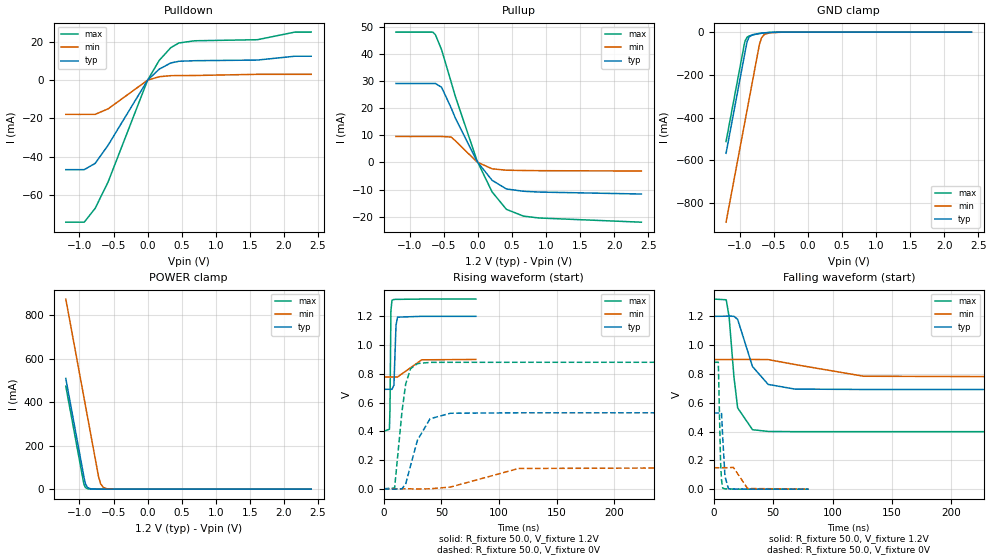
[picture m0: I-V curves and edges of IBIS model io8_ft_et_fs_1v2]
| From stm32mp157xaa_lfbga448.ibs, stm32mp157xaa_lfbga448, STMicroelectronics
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[Model]   io8_ft_et_fs_1v2
Model_type I/O
Polarity   Non-Inverting
Enable   Active-Low
| CAP_THRESHOLD on pad IOFT is "UDTCAPC" :
| Rising=20.00f vddiom   Falling=80.00f vddiom
| C_comp min and max val. don't necessarily correlate with the min and max pvt
| but are the smallest and greatest pad capacitance found.
| var   typ   min   max
C_comp   3.10950pF  3.08865pF  3.12940pF
|C_comp_pullup   1.82115pF  1.58845pF  1.75300pF
|C_comp_pulldown   1.28835pF  1.50020pF  1.37640pF
Vinl = 360.0mV
Vinh = 792.0mV
Vmeas = 600.0mV   | Reference voltage for timing measurements
Cref  = 50.0pF   | Timing specification test load capacitance value
Rref  = 100.0MOhm   | Timing specification test load resistance value
Vref  = 0V   | Timing specification test load voltage
[Model Spec]
| TIME_THRESHOLD on pin ZIV11 is "CMOS" :
| Rising=40.00f vdd   Falling=60.00f vdd
Vinl 463.60000mV 362.60000mV 506.60000mV
Vinh 741.40000mV 545.40000mV 817.40000mV
| variable   typ   min   max
[Temperature Range] 25.0 140.0 -40.0
| variable   typ   min   max
[Voltage Range] 1.2V 900.0mV 1.32V
| variable   typ   min   max
[POWER Clamp Reference] 1.2V 900.0mV 1.32V
| variable   typ   min   max
[GND Clamp Reference] 0V 0V 0V
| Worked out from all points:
|   slope of the pulldown table from 0 to 0.18 V, typ, clamps not added: 30 ohm
|   slope of the pullup table from 0 to 0.18 V, typ, clamps not added: 31.1 ohm
|   GND clamp passes 1 mA (typ) near -0.52 V on its own axis
|   POWER clamp passes 1 mA (typ) near -0.83 V on its own axis
|   rising waveform, R_fixture 50.0, V_fixture 1.2V: 20-80 % time 1.13ns typ, 3.29ns min, 575ps max; typ from 0.692 V to 1.2 V
|   falling waveform, R_fixture 50.0, V_fixture 1.2V: 20-80 % time 12.3ns typ, 33.3ns min, 6.06ns max; typ from 1.2 V to 0.692 V
|   rising waveform, R_fixture 50.0, V_fixture 0V: 20-80 % time 12.3ns typ, 31.1ns min, 6.57ns max; typ from 0 V to 0.529 V
|   falling waveform, R_fixture 50.0, V_fixture 0V: 20-80 % time 2.02ns typ, 4.66ns min, 1.43ns max; typ from 0.529 V to 0 V
[POWER Clamp]
-1.2V     508.8mA    874.1mA    473.5mA
-940mV    66.83mA    432.1mA    31.5mA
-930mV    49.83mA    415.1mA    19.15mA
-910mV    22.88mA    381.1mA    7.077mA
-880mV    7.117mA    330.1mA    1.59mA
-830mV    1.017mA    245.1mA    132uA
-720mV    14.05uA    58.12mA    554nA
-690mV    4.373uA    25.03mA    124.8nA
-650mV    922.5nA    8.136mA    17.23nA
-600mV    132.6nA    1.998mA    1.565nA
-490mV    2.858nA    90.92uA    111.8pA
2.4V      0A         0A         0A
[GND Clamp]
-1.2V     -567.2mA   -889.7mA   -512.2mA
-930mV    -108.2mA   -430.7mA   -53.23mA
-920mV    -91.21mA   -413.7mA   -40.49mA
-890mV    -43.51mA   -362.7mA   -23.59mA
-860mV    -22.57mA   -311.7mA   -17.89mA
-810mV    -12.11mA   -226.7mA   -13.23mA
-710mV    -6.053mA   -57.05mA   -7.064mA
-680mV    -4.908mA   -27.37mA   -5.632mA
-640mV    -3.605mA   -11.51mA   -3.985mA
-560mV    -1.665mA   -3.218mA   -1.61mA
-360mV    -34.72uA   -209.4uA   -9.248uA
2.4V      3.415nA    1.206uA    162.7pA
| variable   typ   min   max
[Pullup Reference] 1.2V 900.0mV 1.32V
| variable   typ   min   max
[Pulldown Reference] 0V 0V 0V
[Pullup]
-1.2V     29.05mA    9.561mA    47.95mA
-660mV    29.05mA    9.561mA    47.95mA
-620mV    29.05mA    9.561mA    46.94mA
-530mV    27.65mA    9.561mA    41.45mA
-390mV    20.07mA    9.347mA    29.59mA
-330mV    16.44mA    8.018mA    24.4mA
-10mV     390.7uA    167.7uA    615.1uA
210mV     -6.527mA   -2.331mA   -10.8mA
420mV     -9.742mA   -2.842mA   -17.23mA
670mV     -10.58mA   -2.95mA    -19.72mA
900mV     -10.88mA   -3.014mA   -20.42mA
2.4V      -11.6mA    -3.141mA   -21.96mA
[Pulldown]
-1.2V     -46.7mA    -17.86mA   -74.13mA
-930mV    -46.7mA    -17.86mA   -74.13mA
-770mV    -43.45mA   -17.86mA   -66.94mA
-580mV    -33.98mA   -14.99mA   -53.18mA
0V        0A         -7pA       0A
170mV     5.742mA    1.791mA    10.3mA
340mV     8.972mA    2.348mA    16.97mA
460mV     9.857mA    2.399mA    19.42mA
690mV     10.15mA    2.431mA    20.56mA
1.61V     10.49mA    3.05mA     21.11mA
2.16V     12.49mA    3.05mA     25.09mA
2.4V      12.49mA    3.05mA     25.09mA
[Ramp]
dV/dt_r 317.39247mV/12.25632ns 89.22182mV/31.10597ns 528.12465mV/6.57236ns
dV/dt_f 304.65151mV/12.34816ns 73.17765mV/33.28345ns 552.41166mV/6.06069ns
R_load = 50.0
| Removed startup time: 0s 0s 0s  .
| Removed end time: 79.9ns.
[Rising Waveform]
R_fixture   = 50.0
V_fixture   = 1.2V
V_fixture_min = 900.0mV
V_fixture_max = 1.32V
0s        692.2mV    778mV      399.3mV
5ns       692.2mV    778mV      414.9mV
5.5ns     692.2mV    778mV      559.5mV
6.3ns     692.3mV    778mV      1.237V
7.2ns     691.9mV    778mV      1.312V
8.9ns     721mV      778mV      1.317V
10.7ns    1.135V     778mV      1.318V
12ns      1.194V     778mV      1.318V
33ns      1.2V       897.3mV    1.32V
79.9ns    1.2V       899.9mV    1.32V
| Removed startup time: 0s 0s 0s  .
| Removed end time: 399.9ns.
[Falling Waveform]
R_fixture   = 50.0
V_fixture   = 1.2V
V_fixture_min = 900.0mV
V_fixture_max = 1.32V
0s        1.2V       900mV      1.32V
10.5ns    1.201V     900mV      1.315V
12.9ns    1.202V     900mV      1.197V
17ns      1.2V       900.7mV    777.2mV
20.1ns    1.179V     900.8mV    564.1mV
32.6ns    851.3mV    900.6mV    412.8mV
45.8ns    727.1mV    899.8mV    400.9mV
68.3ns    695mV      865.5mV    399.3mV
126.1ns   692.2mV    784.1mV    399.3mV
399.9ns   692.2mV    778mV      399.3mV
| Removed startup time: 0s 0s 0s  .
| Removed end time: 399.9ns.
[Rising Waveform]
R_fixture   = 50.0
V_fixture   = 0V
V_fixture_min = 0V
V_fixture_max = 0V
0s        705.9nV    1.001uV    -336.9nV
9.5ns     -2.463mV   1.104uV    6.013mV
15.9ns    303.6uV    1.163uV    538.3mV
19.1ns    34.41mV    -285.2nV   729.4mV
23.3ns    160.5mV    -10.8uV    835.7mV
29.3ns    338.2mV    -1.524mV   871.3mV
40.2ns    487.2mV    68.63uV    879.5mV
57.9ns    525.7mV    12.27mV    880.1mV
117ns     528.8mV    141.5mV    880.2mV
399.9ns   529mV      148.7mV    880.2mV
| Removed startup time: 0s 0s 0s  .
| Removed end time: 79.9ns.
[Falling Waveform]
R_fixture   = 50.0
V_fixture   = 0V
V_fixture_min = 0V
V_fixture_max = 0V
0s        529mV      148.8mV    880.2mV
3.8ns     529mV      148.8mV    881.8mV
5.7ns     531.5mV    148.8mV    190.1mV
6.5ns     532mV      148.8mV    66.18mV
7.5ns     362mV      148.8mV    7.005mV
9.4ns     89.88mV    148.8mV    2.362mV
12.3ns    3.334mV    148.8mV    1.339mV
16.5ns    968.3uV    151.6mV    522uV
28.4ns    336.2uV    4.682mV    61.45uV
79.9ns    -216.7nV   106.4uV    2.402uV
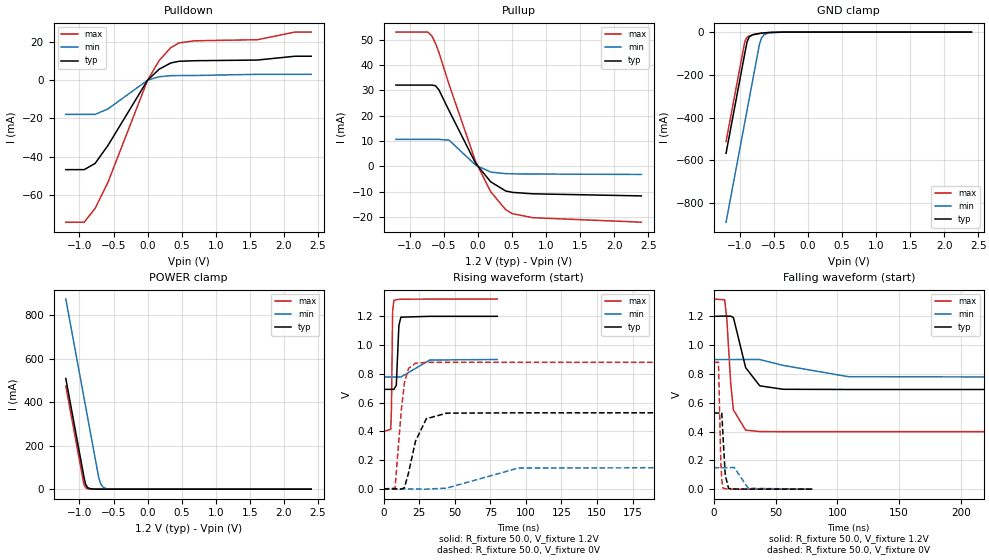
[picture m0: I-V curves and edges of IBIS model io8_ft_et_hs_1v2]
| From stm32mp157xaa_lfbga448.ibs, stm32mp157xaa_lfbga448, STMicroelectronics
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[Model]   io8_ft_et_hs_1v2
Model_type I/O
Polarity   Non-Inverting
Enable   Active-Low
| CAP_THRESHOLD on pad IOFT is "UDTCAPC" :
| Rising=20.00f vddiom   Falling=80.00f vddiom
| C_comp min and max val. don't necessarily correlate with the min and max pvt
| but are the smallest and greatest pad capacitance found.
| var   typ   min   max
C_comp   3.10950pF  3.08870pF  3.12940pF
|C_comp_pullup   1.82115pF  1.58835pF  1.75300pF
|C_comp_pulldown   1.28835pF  1.50035pF  1.37640pF
Vinl = 360.0mV
Vinh = 792.0mV
Vmeas = 600.0mV   | Reference voltage for timing measurements
Cref  = 50.0pF   | Timing specification test load capacitance value
Rref  = 100.0MOhm   | Timing specification test load resistance value
Vref  = 0V   | Timing specification test load voltage
[Model Spec]
| TIME_THRESHOLD on pin ZIV11 is "CMOS" :
| Rising=40.00f vdd   Falling=60.00f vdd
Vinl 463.60000mV 362.60000mV 506.60000mV
Vinh 741.40000mV 545.40000mV 817.40000mV
| variable   typ   min   max
[Temperature Range] 25.0 140.0 -40.0
| variable   typ   min   max
[Voltage Range] 1.2V 900.0mV 1.32V
| variable   typ   min   max
[POWER Clamp Reference] 1.2V 900.0mV 1.32V
| variable   typ   min   max
[GND Clamp Reference] 0V 0V 0V
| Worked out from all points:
|   slope of the pulldown table from 0 to 0.18 V, typ, clamps not added: 30 ohm
|   slope of the pullup table from 0 to 0.18 V, typ, clamps not added: 31.1 ohm
|   GND clamp passes 1 mA (typ) near -0.52 V on its own axis
|   POWER clamp passes 1 mA (typ) near -0.83 V on its own axis
|   rising waveform, R_fixture 50.0, V_fixture 1.2V: 20-80 % time 1.13ns typ, 3.33ns min, 581ps max; typ from 0.692 V to 1.2 V
|   falling waveform, R_fixture 50.0, V_fixture 1.2V: 20-80 % time 9.04ns typ, 24.3ns min, 4.4ns max; typ from 1.2 V to 0.692 V
|   rising waveform, R_fixture 50.0, V_fixture 0V: 20-80 % time 8.16ns typ, 20.6ns min, 4.43ns max; typ from 0 V to 0.529 V
|   falling waveform, R_fixture 50.0, V_fixture 0V: 20-80 % time 2.01ns typ, 4.63ns min, 1.42ns max; typ from 0.529 V to 0 V
[POWER Clamp]
-1.2V     508.8mA    874.1mA    473.5mA
-940mV    66.83mA    432.1mA    31.5mA
-930mV    49.83mA    415.1mA    19.15mA
-910mV    22.88mA    381.1mA    7.077mA
-880mV    7.117mA    330.1mA    1.59mA
-830mV    1.017mA    245.1mA    132uA
-720mV    14.05uA    58.12mA    554nA
-690mV    4.373uA    25.03mA    124.8nA
-650mV    922.5nA    8.136mA    17.23nA
-600mV    132.6nA    1.998mA    1.565nA
-490mV    2.858nA    90.92uA    111.8pA
2.4V      0A         0A         0A
[GND Clamp]
-1.2V     -567.2mA   -889.7mA   -512.2mA
-930mV    -108.2mA   -430.7mA   -53.23mA
-920mV    -91.21mA   -413.7mA   -40.49mA
-890mV    -43.51mA   -362.7mA   -23.59mA
-860mV    -22.57mA   -311.7mA   -17.89mA
-810mV    -12.11mA   -226.7mA   -13.23mA
-710mV    -6.053mA   -57.05mA   -7.064mA
-680mV    -4.908mA   -27.37mA   -5.632mA
-640mV    -3.605mA   -11.51mA   -3.985mA
-560mV    -1.665mA   -3.218mA   -1.61mA
-360mV    -34.72uA   -209.4uA   -9.248uA
2.4V      3.415nA    1.206uA    162.7pA
| variable   typ   min   max
[Pullup Reference] 1.2V 900.0mV 1.32V
| variable   typ   min   max
[Pulldown Reference] 0V 0V 0V
[Pullup]
-1.2V     32.07mA    10.67mA    52.96mA
-730mV    32.07mA    10.67mA    52.96mA
-670mV    32.07mA    10.67mA    51.32mA
-620mV    31.82mA    10.67mA    48.54mA
-570mV    30.22mA    10.67mA    45.01mA
-420mV    21.97mA    10.36mA    32.26mA
-30mV     1.194mA    519uA      1.871mA
190mV     -6.046mA   -2.203mA   -9.95mA
410mV     -9.663mA   -2.836mA   -17.03mA
510mV     -10.21mA   -2.889mA   -18.61mA
810mV     -10.78mA   -2.991mA   -20.19mA
2.4V      -11.6mA    -3.141mA   -21.96mA
[Pulldown]
-1.2V     -46.7mA    -17.86mA   -74.13mA
-930mV    -46.7mA    -17.86mA   -74.13mA
-770mV    -43.45mA   -17.86mA   -66.94mA
-580mV    -33.98mA   -14.99mA   -53.18mA
0V        0A         -7pA       0A
170mV     5.742mA    1.791mA    10.3mA
340mV     8.972mA    2.348mA    16.97mA
460mV     9.857mA    2.399mA    19.42mA
690mV     10.15mA    2.431mA    20.56mA
1.61V     10.49mA    3.05mA     21.11mA
2.16V     12.49mA    3.05mA     25.09mA
2.4V      12.49mA    3.05mA     25.09mA
[Ramp]
dV/dt_r 317.40685mV/8.16413ns 89.2458mV/20.59137ns 528.12535mV/4.43286ns
dV/dt_f 304.65929mV/9.03397ns 73.17635mV/24.3405ns 552.41075mV/4.40029ns
R_load = 50.0
| Removed startup time: 0s 0s 0s  .
| Removed end time: 79.9ns.
[Rising Waveform]
R_fixture   = 50.0
V_fixture   = 1.2V
V_fixture_min = 900.0mV
V_fixture_max = 1.32V
0s        692.2mV    778mV      399.3mV
5ns       692.2mV    778mV      414.9mV
5.5ns     692.2mV    778mV      562mV
6.3ns     692.3mV    778mV      1.236V
7.2ns     691.9mV    778mV      1.311V
8.9ns     721.1mV    778mV      1.316V
10.7ns    1.135V     778mV      1.318V
12.1ns    1.194V     778mV      1.319V
32.4ns    1.2V       896.2mV    1.32V
79.9ns    1.2V       899.9mV    1.32V
| Removed startup time: 0s 0s 0s  .
| Removed end time: 399.9ns.
[Falling Waveform]
R_fixture   = 50.0
V_fixture   = 1.2V
V_fixture_min = 900.0mV
V_fixture_max = 1.32V
0s        1.2V       900mV      1.32V
8.8ns     1.202V     900mV      1.315V
10.6ns    1.201V     900mV      1.178V
13.7ns    1.201V     900mV      737mV
15.9ns    1.192V     900mV      550.3mV
25.8ns    844mV      900.4mV    409.9mV
37.2ns    717.7mV    900.2mV    400.2mV
56.2ns    693.5mV    859.4mV    399.3mV
109.3ns   692.2mV    780.6mV    399.3mV
399.9ns   692.2mV    778mV      399.3mV
| Removed startup time: 0s 0s 0s  .
| Removed end time: 399.9ns.
[Rising Waveform]
R_fixture   = 50.0
V_fixture   = 0V
V_fixture_min = 0V
V_fixture_max = 0V
0s        678.3nV    993.2nV    -351.9nV
8ns       -1.184uV   1.103uV    5.393mV
12.4ns    -1.772mV   1.102uV    548.2mV
14.6ns    7.992mV    1.101uV    736.7mV
17.5ns    112.1mV    -194.9nV   838.7mV
22.4ns    331.8mV    33.33uV    874.1mV
30ns      487.8mV    -1.8mV     879.7mV
44.3ns    526.8mV    5.42mV     880.1mV
94.9ns    528.9mV    145.7mV    880.2mV
399.9ns   529mV      148.7mV    880.2mV
| Removed startup time: 0s 0s 0s  .
| Removed end time: 79.9ns.
[Falling Waveform]
R_fixture   = 50.0
V_fixture   = 0V
V_fixture_min = 0V
V_fixture_max = 0V
0s        529mV      148.8mV    880.2mV
3.8ns     529mV      148.8mV    881.2mV
5.7ns     531.3mV    148.8mV    186.7mV
6.5ns     531.1mV    148.8mV    64.4mV
7.4ns     379.6mV    148.8mV    8.542mV
9.3ns     95.82mV    148.8mV    2.783mV
12ns      4.652mV    148.8mV    1.031mV
16.5ns    1.257mV    151.2mV    291.7uV
27.9ns    207.9uV    5.932mV    20.21uV
79.9ns    611.7nV    56.41uV    983.4nV
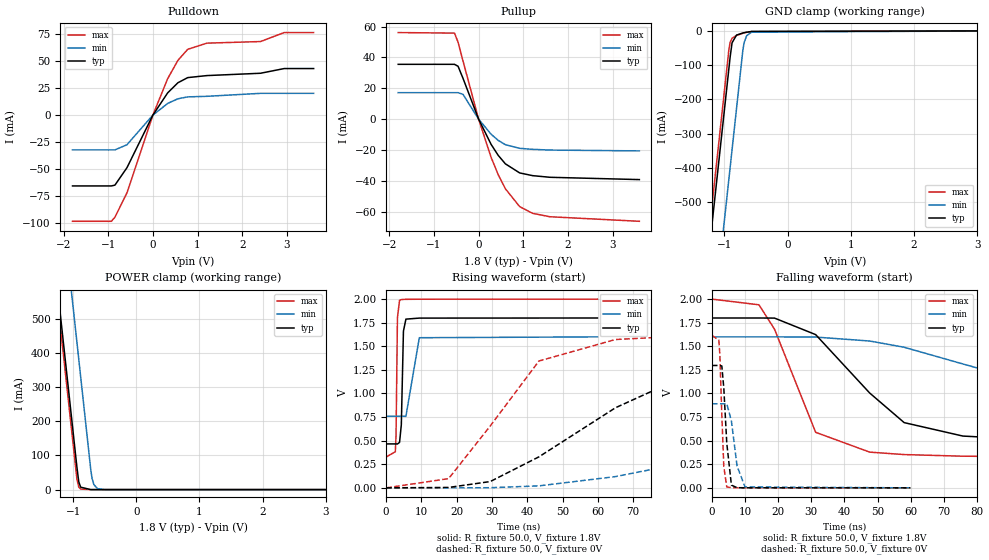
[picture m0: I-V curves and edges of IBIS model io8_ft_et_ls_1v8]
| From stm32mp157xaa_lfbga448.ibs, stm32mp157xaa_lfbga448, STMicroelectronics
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[Model]   io8_ft_et_ls_1v8
Model_type I/O
Polarity   Non-Inverting
Enable   Active-Low
| CAP_THRESHOLD on pad IOFT is "UDTCAPC" :
| Rising=20.00f vddiom   Falling=80.00f vddiom
| C_comp min and max val. don't necessarily correlate with the min and max pvt
| but are the smallest and greatest pad capacitance found.
| var   typ   min   max
C_comp   3.43098pF  3.42356pF  3.49925pF
|C_comp_pullup   1.96705pF  2.05925pF  1.91840pF
|C_comp_pulldown   1.46393pF  1.36431pF  1.58085pF
Vinl = 640.0mV
Vinh = 1.2V
Vmeas = 900.0mV   | Reference voltage for timing measurements
Cref  = 50.0pF   | Timing specification test load capacitance value
Rref  = 100.0MOhm   | Timing specification test load resistance value
Vref  = 0V   | Timing specification test load voltage
[Model Spec]
| TIME_THRESHOLD on pin ZIV11 is "CMOS" :
| Rising=40.00f vdd   Falling=60.00f vdd
Vinl 738.60000mV 665.60000mV 824.60000mV
Vinh 1.04640V 924.40000mV 1.13940V
| variable   typ   min   max
[Temperature Range] 25.0 140.0 -40.0
| variable   typ   min   max
[Voltage Range] 1.8V 1.6V 2.0V
| variable   typ   min   max
[POWER Clamp Reference] 1.8V 1.6V 2.0V
| variable   typ   min   max
[GND Clamp Reference] 0V 0V 0V
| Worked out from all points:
|   slope of the pulldown table from 0 to 0.27 V, typ, clamps not added: 16 ohm
|   slope of the pullup table from 0 to 0.27 V, typ, clamps not added: 17 ohm
|   GND clamp passes 1 mA (typ) near -0.52 V on its own axis
|   POWER clamp passes 1 mA (typ) near -0.83 V on its own axis
|   rising waveform, R_fixture 50.0, V_fixture 1.8V: 20-80 % time 427ps typ, 900ps min, 292ps max; typ from 0.466 V to 1.8 V
|   falling waveform, R_fixture 50.0, V_fixture 1.8V: 20-80 % time 21.4ns typ, 55.5ns min, 10.8ns max; typ from 1.8 V to 0.466 V
|   rising waveform, R_fixture 50.0, V_fixture 0V: 20-80 % time 35.1ns typ, 77.6ns min, 18.5ns max; typ from 0 V to 1.3 V
|   falling waveform, R_fixture 50.0, V_fixture 0V: 20-80 % time 1.35ns typ, 2.08ns min, 940ps max; typ from 1.3 V to 0 V
[POWER Clamp]
-1.8V     1.529A     1.894A     1.494A
-940mV    66.83mA    432.1mA    31.5mA
-910mV    22.88mA    381.1mA    7.077mA
-880mV    7.117mA    330.1mA    1.59mA
-720mV    14.05uA    58.12mA    554nA
-700mV    6.453uA    33.14mA    205nA
-670mV    2.008uA    14.27mA    46.29nA
-610mV    195.5nA    2.645mA    2.508nA
-500mV    3.962nA    120.4uA    139.7pA
3.6V      0A         0A         0A
[GND Clamp]
-1.8V     -1.588A    -1.91A     -1.533A
-1.26V    -670.3mA   -992.4mA   -614.9mA
-1.2V     -568.3mA   -890.4mA   -512.9mA
-930mV    -109.3mA   -431.4mA   -53.86mA
-910mV    -75.33mA   -397.4mA   -32.91mA
-880mV    -34.88mA   -346.4mA   -21.56mA
-810mV    -12.56mA   -227.4mA   -13.55mA
-710mV    -6.275mA   -57.63mA   -7.234mA
-690mV    -5.461mA   -35.21mA   -6.234mA
-650mV    -4.039mA   -14.43mA   -4.463mA
-570mV    -1.908mA   -3.832mA   -1.869mA
3.6V      5.084nA    1.599uA    245.6pA
| variable   typ   min   max
[Pullup Reference] 1.8V 1.6V 2.0V
| variable   typ   min   max
[Pulldown Reference] 0V 0V 0V
[Pullup]
-1.8V     35.55mA    17.17mA    56.15mA
-540mV    35.55mA    17.17mA    55.8mA
-460mV    34.29mA    17.17mA    49.92mA
-350mV    26.53mA    16.1mA     37.8mA
0V        7.41pA     1.33nA     4.294pA
280mV     -16.39mA   -9.814mA   -24.79mA
440mV     -23.55mA   -13.81mA   -36.1mA
600mV     -29.02mA   -16.6mA    -45.2mA
920mV     -34.92mA   -18.96mA   -56.79mA
1.21V     -36.68mA   -19.61mA   -61.13mA
1.6V      -37.75mA   -20.08mA   -63.35mA
3.6V      -39.24mA   -20.63mA   -66.3mA
[Pulldown]
-1.8V     -65.8mA    -32.31mA   -98.64mA
-930mV    -65.8mA    -32.31mA   -98.64mA
-850mV    -65.04mA   -32.31mA   -94.81mA
-580mV    -48.83mA   -27.49mA   -72.14mA
0V        0A         -4pA       0A
330mV     20.59mA    10.79mA    33.74mA
560mV     30.02mA    15.15mA    50.81mA
780mV     34.81mA    16.9mA     61.1mA
1.21V     36.69mA    17.44mA    66.81mA
2.41V     38.85mA    20.19mA    68.31mA
2.94V     43.21mA    20.19mA    76.64mA
3.6V      43.21mA    20.19mA    76.64mA
[Ramp]
dV/dt_r 777.9091mV/35.05865ns 534.07155mV/77.63022ns 970.12301mV/18.51058ns
dV/dt_f 800.59623mV/21.38691ns 504.68342mV/55.54374ns 1.00395V/10.83689ns
R_load = 50.0
| Removed startup time: 0s 0s 0s  .
| Removed end time: 59.9ns.
[Rising Waveform]
R_fixture   = 50.0
V_fixture   = 1.8V
V_fixture_min = 1.6V
V_fixture_max = 2.0V
0s        465.7mV    758.8mV    326.8mV
2.6ns     465.7mV    758.8mV    382.8mV
2.8ns     465.7mV    758.8mV    549.6mV
3.2ns     464.7mV    758.8mV    1.803V
3.8ns     482.2mV    758.8mV    1.988V
4.3ns     669.8mV    758.8mV    1.995V
4.9ns     1.661V     758.9mV    1.997V
5.6ns     1.788V     757.8mV    1.998V
9.4ns     1.799V     1.591V     1.999V
59.9ns    1.8V       1.6V       2V
| Removed startup time: 0s 0s 0s  .
| Removed end time: 499.9ns.
[Falling Waveform]
R_fixture   = 50.0
V_fixture   = 1.8V
V_fixture_min = 1.6V
V_fixture_max = 2.0V
0s        1.8V       1.6V       2V
14.2ns    1.8V       1.6V       1.94V
18.9ns    1.799V     1.6V       1.681V
31.3ns    1.624V     1.598V     588.7mV
47.6ns    1.005V     1.556V     378.6mV
58ns      691.4mV    1.49V      352.8mV
75.7ns    549mV      1.313V     335.5mV
109.6ns   485.9mV    980.8mV    328mV
161.9ns   468.8mV    820.4mV    326.8mV
499.9ns   465.7mV    758.9mV    326.7mV
| Removed startup time: 0s 0s 0s  .
| Removed end time: 499.9ns.
[Rising Waveform]
R_fixture   = 50.0
V_fixture   = 0V
V_fixture_min = 0V
V_fixture_max = 0V
0s        674.6nV    584.2nV    -417.9nV
17.7ns    4.217mV    -80.05uV   97.74mV
29.5ns    66.72mV    1.451mV    655.4mV
43.3ns    328.4mV    20.97mV    1.344V
65ns      848.5mV    119.3mV    1.572V
79.2ns    1.09V      224.3mV    1.599V
95.2ns    1.208V     356.2mV    1.61V
142.1ns   1.284V     673.6mV    1.617V
190.8ns   1.295V     820.1mV    1.617V
499.9ns   1.297V     890.1mV    1.617V
| Removed startup time: 0s 0s 0s  .
| Removed end time: 59.9ns.
[Falling Waveform]
R_fixture   = 50.0
V_fixture   = 0V
V_fixture_min = 0V
V_fixture_max = 0V
0s        1.297V     890.4mV    1.617V
2.1ns     1.297V     890.4mV    1.565V
2.4ns     1.296V     890.4mV    1.418V
3ns       1.292V     890.4mV    777.8mV
3.6ns     1.059V     890.4mV    226.5mV
4.5ns     471mV      893.5mV    9.77mV
5.9ns     28.78mV    706.6mV    2.065mV
7.6ns     1.869mV    231.5mV    1.317mV
10ns      814.2uV    9.749mV    1.005mV
59.9ns    102uV      193.7uV    43.17uV
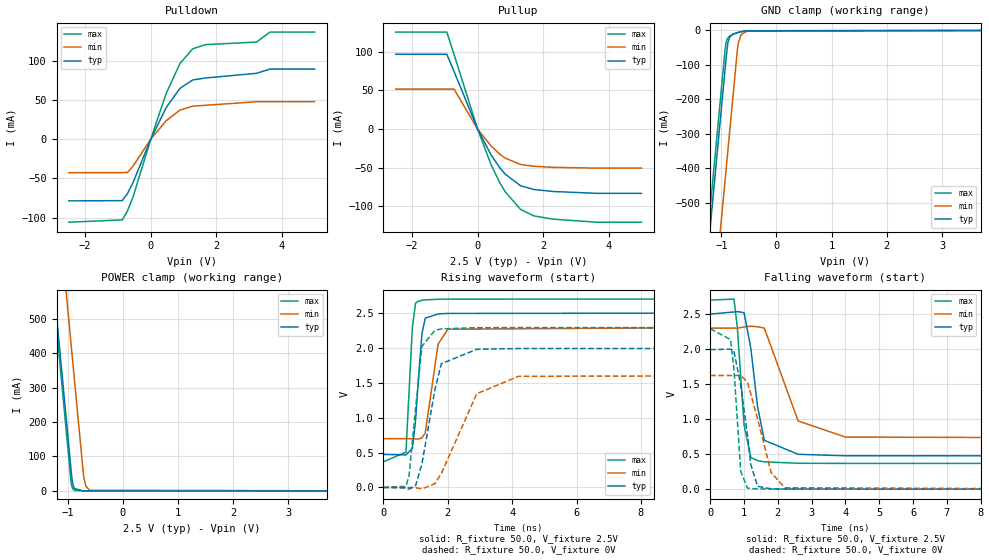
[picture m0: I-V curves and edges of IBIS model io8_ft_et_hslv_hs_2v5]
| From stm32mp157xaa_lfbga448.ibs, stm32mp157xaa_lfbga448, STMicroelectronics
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[Model]   io8_ft_et_hslv_hs_2v5
Model_type I/O
Polarity   Non-Inverting
Enable   Active-Low
| CAP_THRESHOLD on pad IOFT is "UDTCAPC" :
| Rising=20.00f vddiom   Falling=80.00f vddiom
| C_comp min and max val. don't necessarily correlate with the min and max pvt
| but are the smallest and greatest pad capacitance found.
| var   typ   min   max
C_comp   3.59839pF  3.56215pF  3.65635pF
|C_comp_pullup   2.12240pF  2.18495pF  2.03935pF
|C_comp_pulldown   1.47599pF  1.37720pF  1.61700pF
Vinl = 920.0mV
Vinh = 1.62V
Vmeas = 1.25V   | Reference voltage for timing measurements
Cref  = 50.0pF   | Timing specification test load capacitance value
Rref  = 100.0MOhm   | Timing specification test load resistance value
Vref  = 0V   | Timing specification test load voltage
[Model Spec]
| TIME_THRESHOLD on pin ZIV11 is "CMOS" :
| Rising=40.00f vdd   Falling=60.00f vdd
Vinl 1.03860V 964.60000mV 1.11860V
Vinh 1.36340V 1.26240V 1.44140V
| variable   typ   min   max
[Temperature Range] 25.0 140.0 -40.0
| variable   typ   min   max
[Voltage Range] 2.5V 2.3V 2.7V
| variable   typ   min   max
[POWER Clamp Reference] 2.5V 2.3V 2.7V
| variable   typ   min   max
[GND Clamp Reference] 0V 0V 0V
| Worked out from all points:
|   slope of the pulldown table from 0 to 0.375 V, typ, clamps not added: 11.3 ohm
|   slope of the pullup table from 0 to 0.375 V, typ, clamps not added: 12.3 ohm
|   GND clamp passes 1 mA (typ) near -0.52 V on its own axis
|   POWER clamp passes 1 mA (typ) near -0.83 V on its own axis
|   rising waveform, R_fixture 50.0, V_fixture 2.5V: 20-80 % time 200ps typ, 261ps min, 151ps max; typ from 0.473 V to 2.5 V
|   falling waveform, R_fixture 50.0, V_fixture 2.5V: 20-80 % time 323ps typ, 661ps min, 212ps max; typ from 2.5 V to 0.473 V
|   rising waveform, R_fixture 50.0, V_fixture 0V: 20-80 % time 462ps typ, 914ps min, 287ps max; typ from 0 V to 1.99 V
|   falling waveform, R_fixture 50.0, V_fixture 0V: 20-80 % time 323ps typ, 518ps min, 198ps max; typ from 1.99 V to 0 V
[POWER Clamp]
-2.5V     2.719A     3.084A     2.683A
-1.38V    814.8mA    1.18A      779.5mA
-1.28V    644.8mA    1.01A      609.5mA
-1.07V    287.8mA    653.1mA    252.5mA
-940mV    66.83mA    432.1mA    31.5mA
-930mV    49.83mA    415.1mA    19.15mA
-910mV    22.88mA    381.1mA    7.077mA
-880mV    7.117mA    330.1mA    1.59mA
-710mV    9.523uA    43.89mA    337nA
-670mV    2.009uA    14.27mA    46.32nA
-600mV    133.1nA    1.998mA    1.613nA
5V        0A         0A         0A
[GND Clamp]
-2.5V     -2.779A    -3.101A    -2.723A
-1.26V    -670.8mA   -992.7mA   -614.5mA
-930mV    -109.8mA   -431.7mA   -53.54mA
-910mV    -75.83mA   -397.7mA   -32.67mA
-880mV    -35.28mA   -346.7mA   -21.39mA
-850mV    -20.07mA   -295.7mA   -16.99mA
-790mV    -10.9mA    -193.7mA   -12.02mA
-710mV    -6.374mA   -57.93mA   -7.219mA
-690mV    -5.545mA   -35.45mA   -6.225mA
-640mV    -3.775mA   -11.96mA   -4.068mA
-540mV    -1.354mA   -2.661mA   -1.223mA
5V        7.033nA    2.148uA    347.4pA
| variable   typ   min   max
[Pullup Reference] 2.5V 2.3V 2.7V
| variable   typ   min   max
[Pulldown Reference] 0V 0V 0V
[Pullup]
-2.5V     96.71mA    51.69mA    125.4mA
-940mV    96.71mA    51.69mA    125.4mA
-720mV    74.67mA    51.69mA    96.58mA
0V        9.19pA     1.4nA      5.79pA
410mV     -33.27mA   -21.82mA   -45.98mA
680mV     -50.17mA   -32.54mA   -69.6mA
840mV     -58.2mA    -37.47mA   -80.99mA
1.31V     -73.24mA   -45.77mA   -103.8mA
1.71V     -78.05mA   -48.05mA   -112.2mA
2.29V     -80.67mA   -49.47mA   -116.4mA
3.63V     -83.07mA   -50.51mA   -120.4mA
5V        -83.07mA   -50.51mA   -120.4mA
[Pulldown]
-2.5V     -78.63mA   -42.6mA    -105.8mA
-870mV    -78.28mA   -42.6mA    -102.9mA
-710mV    -69.32mA   -42.37mA   -91.24mA
-540mV    -55.23mA   -34.22mA   -73.64mA
0V        0A         -3pA       10fA
470mV     40.29mA    23.69mA    58.27mA
890mV     64.85mA    37.11mA    96.49mA
1.28V     75.62mA    42.24mA    115.4mA
1.67V     78.14mA    43.3mA     120.7mA
3.23V     84.11mA    47.89mA    124mA
3.64V     89.51mA    47.89mA    136.7mA
5V        89.51mA    47.89mA    136.7mA
[Ramp]
dV/dt_r 1.19557V/459.39233ps 973.59944mV/910.50009ps 1.37498V/274.75527ps
dV/dt_f 1.21605V/318.55635ps 960.47162mV/655.26821ps 1.39952V/201.72225ps
R_load = 50.0
| Removed startup time: 0s 0s 0s  .
| Removed end time: 12.9ns.
[Rising Waveform]
R_fixture   = 50.0
V_fixture   = 2.5V
V_fixture_min = 2.3V
V_fixture_max = 2.7V
0s        473.2mV    699.2mV    367.5mV
700ps     466mV      699.2mV    505.3mV
900ps     561.3mV    699.7mV    2.294V
1ns       959.7mV    695.6mV    2.642V
1.1ns     1.633V     694.1mV    2.672V
1.2ns     2.21V      711.4mV    2.683V
1.3ns     2.426V     781.5mV    2.688V
1.7ns     2.487V     2.054V     2.697V
2ns       2.494V     2.267V     2.699V
12.9ns    2.5V       2.3V       2.7V
| Removed startup time: 0s 0s 0s  .
| Removed end time: 35.9ns.
[Falling Waveform]
R_fixture   = 50.0
V_fixture   = 2.5V
V_fixture_min = 2.3V
V_fixture_max = 2.7V
0s        2.5V       2.3V       2.7V
700ps     2.531V     2.3V       2.715V
800ps     2.536V     2.299V     2.313V
1ns       2.52V      2.317V     918.7mV
1.2ns     2.012V     2.328V     452.7mV
1.4ns     1.175V     2.319V     407.8mV
1.6ns     697.7mV    2.3V       390.7mV
2.6ns     498.1mV    973.7mV    369.9mV
4ns       476.5mV    744.3mV    367.8mV
35.9ns    473.2mV    699.2mV    367.5mV
| Removed startup time: 0s 0s 0s  .
| Removed end time: 35.9ns.
[Rising Waveform]
R_fixture   = 50.0
V_fixture   = 0V
V_fixture_min = 0V
V_fixture_max = 0V
0s        50.41nV    -366nV     -6.381uV
700ps     -8.405mV   -165.7uV   14.5mV
800ps     -24.9mV    -148.8uV   177.8mV
1ns       27.11mV    -3.101mV   1.137V
1.2ns     341.7mV    -21.82mV   2.023V
1.6ns     1.403V     54.6mV     2.252V
1.8ns     1.773V     199.8mV    2.272V
2.9ns     1.98V      1.343V     2.29V
4.2ns     1.991V     1.593V     2.291V
35.9ns    1.993V     1.623V     2.292V
| Removed startup time: 0s 0s 0s  .
| Removed end time: 12.9ns.
[Falling Waveform]
R_fixture   = 50.0
V_fixture   = 0V
V_fixture_min = 0V
V_fixture_max = 0V
0s        1.993V     1.623V     2.292V
600ps     2V         1.623V     2.136V
700ps     1.971V     1.622V     1.719V
900ps     1.487V     1.629V     257.5mV
1.1ns     775mV      1.527V     14.59mV
1.2ns     351.5mV    1.359V     7.748mV
1.4ns     40.6mV     1.003V     3.886mV
1.8ns     4.779mV    239.4mV    2.09mV
2.2ns     2.674mV    21.12mV    1.122mV
12.9ns    17.76uV    39.62uV    6.471uV
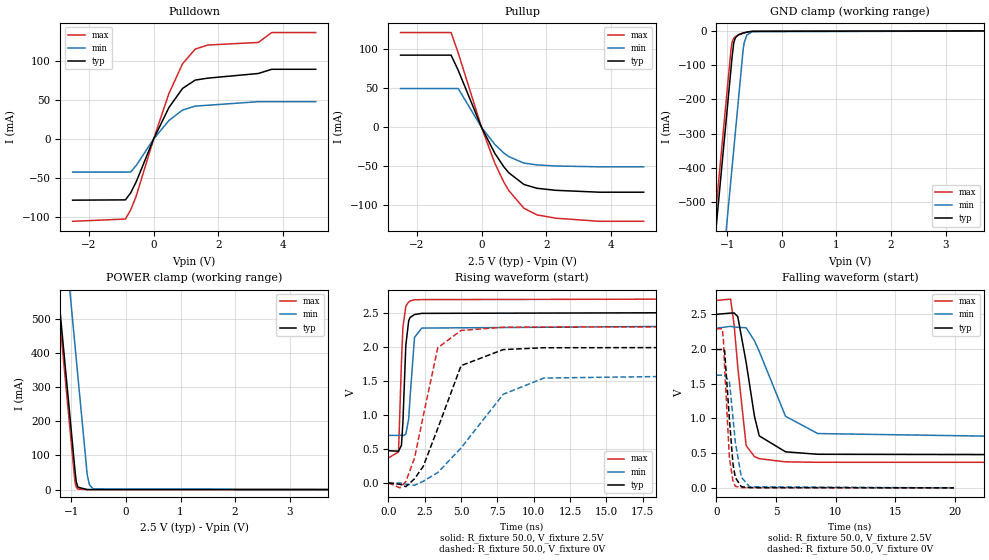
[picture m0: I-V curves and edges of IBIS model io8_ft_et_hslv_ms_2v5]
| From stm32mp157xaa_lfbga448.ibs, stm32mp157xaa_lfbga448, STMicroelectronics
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[Model]   io8_ft_et_hslv_ms_2v5
Model_type I/O
Polarity   Non-Inverting
Enable   Active-Low
| CAP_THRESHOLD on pad IOFT is "UDTCAPC" :
| Rising=20.00f vddiom   Falling=80.00f vddiom
| C_comp min and max val. don't necessarily correlate with the min and max pvt
| but are the smallest and greatest pad capacitance found.
| var   typ   min   max
C_comp   3.59839pF  3.56215pF  3.65635pF
|C_comp_pullup   2.12240pF  2.18495pF  2.03935pF
|C_comp_pulldown   1.47599pF  1.37720pF  1.61700pF
Vinl = 920.0mV
Vinh = 1.62V
Vmeas = 1.25V   | Reference voltage for timing measurements
Cref  = 50.0pF   | Timing specification test load capacitance value
Rref  = 100.0MOhm   | Timing specification test load resistance value
Vref  = 0V   | Timing specification test load voltage
[Model Spec]
| TIME_THRESHOLD on pin ZIV11 is "CMOS" :
| Rising=40.00f vdd   Falling=60.00f vdd
Vinl 1.03860V 964.60000mV 1.11860V
Vinh 1.36340V 1.26240V 1.44140V
| variable   typ   min   max
[Temperature Range] 25.0 140.0 -40.0
| variable   typ   min   max
[Voltage Range] 2.5V 2.3V 2.7V
| variable   typ   min   max
[POWER Clamp Reference] 2.5V 2.3V 2.7V
| variable   typ   min   max
[GND Clamp Reference] 0V 0V 0V
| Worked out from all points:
|   slope of the pulldown table from 0 to 0.375 V, typ, clamps not added: 11.3 ohm
|   slope of the pullup table from 0 to 0.375 V, typ, clamps not added: 12.3 ohm
|   GND clamp passes 1 mA (typ) near -0.52 V on its own axis
|   POWER clamp passes 1 mA (typ) near -0.83 V on its own axis
|   rising waveform, R_fixture 50.0, V_fixture 2.5V: 20-80 % time 232ps typ, 273ps min, 230ps max; typ from 0.473 V to 2.5 V
|   falling waveform, R_fixture 50.0, V_fixture 2.5V: 20-80 % time 1.14ns typ, 2.29ns min, 739ps max; typ from 2.5 V to 0.473 V
|   rising waveform, R_fixture 50.0, V_fixture 0V: 20-80 % time 1.92ns typ, 3.56ns min, 1.28ns max; typ from 0 V to 1.99 V
|   falling waveform, R_fixture 50.0, V_fixture 0V: 20-80 % time 498ps typ, 638ps min, 413ps max; typ from 1.99 V to 0 V
[POWER Clamp]
-2.5V     2.719A     3.084A     2.683A
-1.38V    814.8mA    1.18A      779.5mA
-1.28V    644.8mA    1.01A      609.5mA
-1.07V    287.8mA    653.1mA    252.5mA
-940mV    66.83mA    432.1mA    31.5mA
-930mV    49.83mA    415.1mA    19.15mA
-910mV    22.88mA    381.1mA    7.077mA
-880mV    7.117mA    330.1mA    1.59mA
-710mV    9.523uA    43.89mA    337nA
-670mV    2.009uA    14.27mA    46.32nA
-600mV    133.1nA    1.998mA    1.613nA
5V        0A         0A         0A
[GND Clamp]
-2.5V     -2.779A    -3.101A    -2.723A
-1.26V    -670.8mA   -992.7mA   -614.5mA
-930mV    -109.8mA   -431.7mA   -53.54mA
-910mV    -75.83mA   -397.7mA   -32.67mA
-880mV    -35.28mA   -346.7mA   -21.39mA
-850mV    -20.07mA   -295.7mA   -16.99mA
-790mV    -10.9mA    -193.7mA   -12.02mA
-710mV    -6.374mA   -57.93mA   -7.219mA
-690mV    -5.545mA   -35.45mA   -6.225mA
-640mV    -3.775mA   -11.96mA   -4.068mA
-540mV    -1.354mA   -2.661mA   -1.223mA
5V        7.033nA    2.148uA    347.4pA
| variable   typ   min   max
[Pullup Reference] 2.5V 2.3V 2.7V
| variable   typ   min   max
[Pulldown Reference] 0V 0V 0V
[Pullup]
-2.5V     92.74mA    49.91mA    121.7mA
-940mV    92.74mA    49.91mA    121.7mA
-720mV    73.28mA    49.91mA    95.49mA
0V        9.19pA     1.4nA      5.79pA
410mV     -33.27mA   -21.81mA   -45.98mA
680mV     -50.17mA   -32.54mA   -69.6mA
840mV     -58.2mA    -37.46mA   -80.99mA
1.31V     -73.24mA   -45.77mA   -103.8mA
1.71V     -78.05mA   -48.05mA   -112.2mA
2.29V     -80.67mA   -49.47mA   -116.4mA
3.63V     -83.07mA   -50.51mA   -120.4mA
5V        -83.07mA   -50.51mA   -120.4mA
[Pulldown]
-2.5V     -78.63mA   -42.6mA    -105.8mA
-870mV    -78.28mA   -42.6mA    -102.9mA
-710mV    -69.32mA   -42.37mA   -91.24mA
-540mV    -55.23mA   -34.22mA   -73.64mA
0V        0A         -3pA       10fA
470mV     40.29mA    23.69mA    58.27mA
890mV     64.85mA    37.11mA    96.49mA
1.28V     75.62mA    42.24mA    115.4mA
1.67V     78.14mA    43.3mA     120.7mA
3.23V     84.11mA    47.89mA    124mA
3.64V     89.51mA    47.89mA    136.7mA
5V        89.51mA    47.89mA    136.7mA
[Ramp]
dV/dt_r 1.19556V/1.92236ns 973.56114mV/3.56353ns 1.37498V/1.27815ns
dV/dt_f 1.21605V/1.1335ns 960.46991mV/2.2796ns 1.39953V/737.16036ps
R_load = 50.0
| Removed startup time: 0s 0s 0s  .
| Removed end time: 19.9ns.
[Rising Waveform]
R_fixture   = 50.0
V_fixture   = 2.5V
V_fixture_min = 2.3V
V_fixture_max = 2.7V
0s        473.2mV    699.2mV    367.5mV
700ps     467.1mV    699.2mV    456.2mV
900ps     553.4mV    699.5mV    1.771V
1ns       889.4mV    695.2mV    2.284V
1.2ns     2.02V      714.7mV    2.597V
1.4ns     2.385V     943.8mV    2.659V
1.5ns     2.432V     1.281V     2.673V
1.8ns     2.474V     2.139V     2.69V
2.3ns     2.491V     2.275V     2.693V
19.9ns    2.5V       2.3V       2.7V
| Removed startup time: 0s 0s 0s  .
| Removed end time: 39.9ns.
[Falling Waveform]
R_fixture   = 50.0
V_fixture   = 2.5V
V_fixture_min = 2.3V
V_fixture_max = 2.7V
0s        2.5V       2.3V       2.7V
1.2ns     2.518V     2.327V     2.719V
1.5ns     2.519V     2.316V     2.338V
1.8ns     2.467V     2.313V     1.742V
2.5ns     1.808V     2.307V     609.8mV
3.2ns     1.029V     2.118V     448.9mV
3.6ns     748.7mV    1.965V     420.4mV
5.8ns     519.3mV    1.031V     374.6mV
8.5ns     483.7mV    782.4mV    368.5mV
39.9ns    473.2mV    699.2mV    367.5mV
| Removed startup time: 0s 0s 0s  .
| Removed end time: 39.9ns.
[Rising Waveform]
R_fixture   = 50.0
V_fixture   = 0V
V_fixture_min = 0V
V_fixture_max = 0V
0s        191.7nV    -253.4nV   -5.973uV
800ps     -19.27mV   -65.39uV   -71.67mV
1.2ns     -54.11mV   -17.21mV   20.99mV
1.8ns     61.29mV    -33.6mV    367.3mV
2.4ns     244.9mV    25.23mV    985.1mV
3.4ns     801.9mV    152.6mV    1.986V
5ns       1.723V     514.3mV    2.24V
7.9ns     1.959V     1.302V     2.287V
10.7ns    1.986V     1.541V     2.291V
39.9ns    1.993V     1.623V     2.292V
| Removed startup time: 0s 0s 0s  .
| Removed end time: 19.9ns.
[Falling Waveform]
R_fixture   = 50.0
V_fixture   = 0V
V_fixture_min = 0V
V_fixture_max = 0V
0s        1.993V     1.623V     2.292V
500ps     1.993V     1.623V     2.292V
600ps     2.002V     1.623V     2.135V
700ps     1.972V     1.622V     1.729V
1.1ns     987.3mV    1.53V      427.1mV
1.4ns     339.7mV    1.005V     96.97mV
1.6ns     147mV      653mV      22.5mV
2.1ns     16.07mV    152.8mV    4.278mV
2.8ns     4.149mV    15.04mV    2.281mV
19.9ns    5.321uV    25.35uV    -415.4nV
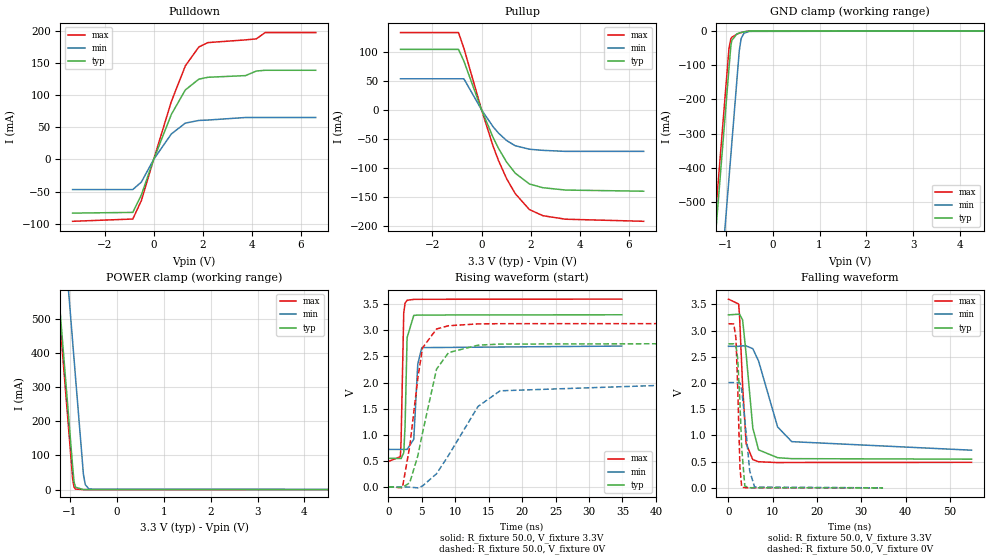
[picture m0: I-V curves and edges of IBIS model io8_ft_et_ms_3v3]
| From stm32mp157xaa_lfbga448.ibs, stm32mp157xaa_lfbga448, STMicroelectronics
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[Model]   io8_ft_et_ms_3v3
Model_type I/O
Polarity   Non-Inverting
Enable   Active-Low
| CAP_THRESHOLD on pad IOFT is "UDTCAPC" :
| Rising=20.00f vddiom   Falling=80.00f vddiom
| C_comp min and max val. don't necessarily correlate with the min and max pvt
| but are the smallest and greatest pad capacitance found.
| var   typ   min   max
C_comp   3.68632pF  3.64973pF  3.70805pF
|C_comp_pullup   2.21620pF  2.27950pF  2.11835pF
|C_comp_pulldown   1.47012pF  1.37023pF  1.58970pF
Vinl = 1.08V
Vinh = 2.16V
Vmeas = 1.65V   | Reference voltage for timing measurements
Cref  = 50.0pF   | Timing specification test load capacitance value
Rref  = 100.0MOhm   | Timing specification test load resistance value
Vref  = 0V   | Timing specification test load voltage
[Model Spec]
| TIME_THRESHOLD on pin ZIV11 is "CMOS" :
| Rising=40.00f vdd   Falling=60.00f vdd
Vinl 1.36060V 1.12960V 1.47360V
Vinh 1.71540V 1.45040V 1.82940V
| variable   typ   min   max
[Temperature Range] 25.0 140.0 -40.0
| variable   typ   min   max
[Voltage Range] 3.3V 2.7V 3.6V
| variable   typ   min   max
[POWER Clamp Reference] 3.3V 2.7V 3.6V
| variable   typ   min   max
[GND Clamp Reference] 0V 0V 0V
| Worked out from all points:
|   slope of the pulldown table from 0 to 0.495 V, typ, clamps not added: 9.86 ohm
|   slope of the pullup table from 0 to 0.495 V, typ, clamps not added: 9.93 ohm
|   GND clamp passes 1 mA (typ) near -0.52 V on its own axis
|   POWER clamp passes 1 mA (typ) near -0.83 V on its own axis
|   rising waveform, R_fixture 50.0, V_fixture 3.3V: 20-80 % time 295ps typ, 426ps min, 262ps max; typ from 0.547 V to 3.3 V
|   falling waveform, R_fixture 50.0, V_fixture 3.3V: 20-80 % time 1.78ns typ, 4.1ns min, 1.1ns max; typ from 3.3 V to 0.547 V
|   rising waveform, R_fixture 50.0, V_fixture 0V: 20-80 % time 2.74ns typ, 5.79ns min, 1.83ns max; typ from 0 V to 2.75 V
|   falling waveform, R_fixture 50.0, V_fixture 0V: 20-80 % time 830ps typ, 1.28ns min, 613ps max; typ from 2.75 V to 0 V
[POWER Clamp]
-3.3V     4.079A     4.444A     4.043A
-1.46V    950.8mA    1.316A     915.5mA
-1.28V    644.8mA    1.01A      609.5mA
-1.09V    321.8mA    687.1mA    286.5mA
-1.07V    287.8mA    653.1mA    252.5mA
-940mV    66.83mA    432.1mA    31.5mA
-910mV    22.88mA    381.1mA    7.077mA
-880mV    7.117mA    330.1mA    1.59mA
-710mV    9.525uA    43.89mA    337.5nA
-670mV    2.01uA     14.27mA    46.78nA
-590mV    92.5nA     1.508mA    1.507nA
6.6V      0A         0A         0A
[GND Clamp]
-3.3V     -4.139A    -4.461A    -4.081A
-1.26V    -670.8mA   -992.8mA   -613.3mA
-1.1V     -398.8mA   -720.8mA   -341.3mA
-930mV    -109.8mA   -431.8mA   -52.32mA
-890mV    -44.91mA   -363.8mA   -23.04mA
-870mV    -28.43mA   -329.8mA   -18.86mA
-760mV    -8.879mA   -142.8mA   -9.749mA
-710mV    -6.383mA   -58.04mA   -7.036mA
-670mV    -4.798mA   -22.41mA   -5.193mA
-610mV    -2.902mA   -7.057mA   -2.962mA
-500mV    -778.4uA   -1.643mA   -611.3uA
6.6V      9.268nA    3.087uA    468pA
| variable   typ   min   max
[Pullup Reference] 3.3V 2.7V 3.6V
| variable   typ   min   max
[Pulldown Reference] 0V 0V 0V
[Pullup]
-3.3V     104.1mA    53.5mA     133.1mA
-940mV    104.1mA    53.5mA     133.1mA
-720mV    83.95mA    53.5mA     106.1mA
0V        11.24pA    1.438nA    7.78pA
470mV     -47.64mA   -29.17mA   -62.71mA
690mV     -66.39mA   -40.06mA   -87.4mA
1.02V     -89.98mA   -52.88mA   -118.5mA
1.37V     -109mA     -61.77mA   -144.2mA
1.95V     -127.7mA   -67.79mA   -171.8mA
2.5V      -134.1mA   -69.74mA   -182.3mA
3.42V     -138.1mA   -71.49mA   -188.3mA
6.6V      -140.1mA   -71.49mA   -191.9mA
[Pulldown]
-3.3V     -83.56mA   -46.9mA    -96.31mA
-850mV    -82.46mA   -46.9mA    -92.78mA
-500mV    -55.19mA   -35.23mA   -63.97mA
0V        30fA       -2pA       200fA
720mV     70.07mA    39.69mA    90.11mA
1.29V     108.2mA    56.55mA    145.7mA
1.84V     125mA      60.7mA     175.1mA
2.21V     127.9mA    61.3mA     181.9mA
3.74V     130.5mA    65.29mA    186.1mA
4.18V     137.6mA    65.29mA    187.7mA
4.54V     138.8mA    65.29mA    197.5mA
6.6V      138.8mA    65.29mA    197.5mA
[Ramp]
dV/dt_r 1.64856V/2.74012ns 1.20469V/5.79217ns 1.87853V/1.83118ns
dV/dt_f 1.65162V/1.77606ns 1.18888V/4.09416ns 1.86819V/1.09811ns
R_load = 50.0
| Removed startup time: 0s 0s 0s  .
| Removed end time: 34.9ns.
[Rising Waveform]
R_fixture   = 50.0
V_fixture   = 3.3V
V_fixture_min = 2.7V
V_fixture_max = 3.6V
0s        547.3mV    718.4mV    486.3mV
1.8ns     544.2mV    718.4mV    579.7mV
1.9ns     543.1mV    718.4mV    875.1mV
2.3ns     653.5mV    718.4mV    3.335V
2.5ns     1.168V     718.5mV    3.525V
2.8ns     2.863V     717.8mV    3.578V
3.8ns     3.288V     913.4mV    3.595V
4.4ns     3.294V     2.357V     3.596V
5ns       3.295V     2.67V      3.597V
34.9ns    3.3V       2.7V       3.6V
| Removed startup time: 0s 0s 0s  .
| Removed end time: 54.9ns.
[Falling Waveform]
R_fixture   = 50.0
V_fixture   = 3.3V
V_fixture_min = 2.7V
V_fixture_max = 3.6V
0s        3.3V       2.7V       3.6V
2.3ns     3.312V     2.699V     3.507V
2.5ns     3.311V     2.703V     3.294V
3.2ns     3.204V     2.709V     1.946V
4ns       2.548V     2.708V     842.1mV
5.5ns     1.144V     2.655V     538.3mV
6.8ns     724.6mV    2.42V      498.7mV
11.1ns    575.7mV    1.162V     482mV
14.3ns    557mV      881.5mV    484.3mV
54.9ns    547.3mV    718.5mV    486.3mV
| Removed startup time: 0s 0s 0s  .
| Removed end time: 54.9ns.
[Rising Waveform]
R_fixture   = 50.0
V_fixture   = 0V
V_fixture_min = 0V
V_fixture_max = 0V
0s        615.3nV    462.9nV    -464nV
2.1ns     -12.22mV   -1.561uV   -17.02mV
3.2ns     79.81mV    -4.672mV   779.7mV
4.4ns     593.4mV    -18.97mV   2.077V
5.1ns     1.031V     15.99mV    2.663V
7.2ns     2.256V     251.3mV    3.027V
9ns       2.575V     604mV      3.09V
13.4ns    2.717V     1.541V     3.125V
16.7ns    2.738V     1.842V     3.129V
54.9ns    2.748V     2.008V     3.131V
| Removed startup time: 0s 0s 0s  .
| Removed end time: 34.9ns.
[Falling Waveform]
R_fixture   = 50.0
V_fixture   = 0V
V_fixture_min = 0V
V_fixture_max = 0V
0s        2.748V     2.008V     3.131V
1.2ns     2.747V     2.008V     3.127V
1.7ns     2.707V     2.008V     2.854V
2.1ns     2.465V     2.008V     1.887V
2.6ns     1.612V     2.002V     383.4mV
3ns       750.4mV    1.872V     11.64mV
3.7ns     34.28mV    1.301V     3.107mV
4.8ns     3.283mV    325.7mV    1.711mV
5.9ns     1.922mV    16.44mV    1.21mV
34.9ns    439.6nV    28.95uV    980.8nV
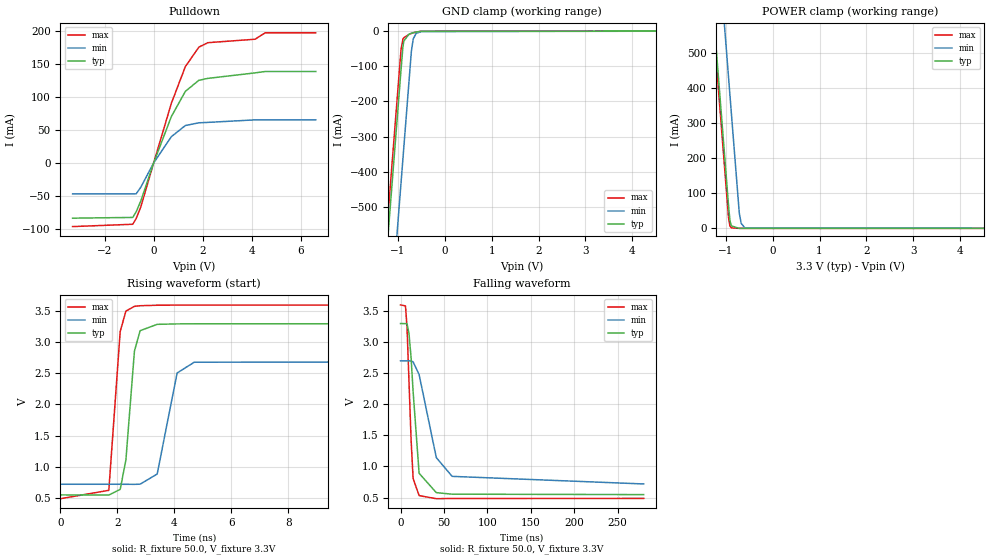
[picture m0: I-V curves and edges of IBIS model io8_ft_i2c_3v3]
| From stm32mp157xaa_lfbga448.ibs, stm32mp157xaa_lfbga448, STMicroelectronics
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[Model]   io8_ft_i2c_3v3
Model_type I/O_open_drain
Polarity   Non-Inverting
Enable   Active-Low
| CAP_THRESHOLD on pad IOFT is "UDTCAPC" :
| Rising=20.00f vddiom   Falling=80.00f vddiom
| C_comp min and max val. don't necessarily correlate with the min and max pvt
| but are the smallest and greatest pad capacitance found.
| var   typ   min   max
C_comp   3.70648pF  3.67113pF  3.73223pF
|C_comp_pulldown   3.70648pF  3.67113pF  3.73223pF
Vinl = 1.08V
Vinh = 2.16V
Vmeas = 1.65V   | Reference voltage for timing measurements
Cref  = 50.0pF   | Timing specification test load capacitance value
Rref  = 100.0MOhm   | Timing specification test load resistance value
Vref  = 1.65V   | Timing specification test load voltage
[Model Spec]
| TIME_THRESHOLD on pin ZIV11 is "CMOS" :
| Rising=40.00f vdd   Falling=60.00f vdd
Vinl 1.36060V 1.12960V 1.47360V
Vinh 1.71640V 1.45140V 1.83040V
| variable   typ   min   max
[Temperature Range] 25.0 140.0 -40.0
| variable   typ   min   max
[Voltage Range] 3.3V 2.7V 3.6V
| variable   typ   min   max
[POWER Clamp Reference] 3.3V 2.7V 3.6V
| variable   typ   min   max
[GND Clamp Reference] 0V 0V 0V
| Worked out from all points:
|   slope of the pulldown table from 0 to 0.495 V, typ, clamps not added: 9.86 ohm
|   GND clamp passes 1 mA (typ) near -0.52 V on its own axis
|   POWER clamp passes 1 mA (typ) near -0.83 V on its own axis
|   rising waveform, R_fixture 50.0, V_fixture 3.3V: 20-80 % time 281ps typ, 398ps min, 259ps max; typ from 0.547 V to 3.3 V
|   falling waveform, R_fixture 50.0, V_fixture 3.3V: 20-80 % time 7.51ns typ, 17.3ns min, 4.93ns max; typ from 3.3 V to 0.547 V
[POWER Clamp]
-3.3V     4.079A     4.444A     4.043A
-1.46V    950.8mA    1.316A     915.5mA
-1.28V    644.8mA    1.01A      609.5mA
-1.1V     338.8mA    704.1mA    303.5mA
-1.09V    321.8mA    687.1mA    286.5mA
-940mV    66.83mA    432.1mA    31.5mA
-910mV    22.88mA    381.1mA    7.077mA
-880mV    7.117mA    330.1mA    1.59mA
-710mV    9.523uA    43.89mA    337nA
-670mV    2.009uA    14.27mA    46.35nA
-590mV    90.76nA    1.508mA    1.088nA
6.6V      0A         0A         0A
[GND Clamp]
-3.3V     -4.139A    -4.461A    -4.081A
-1.26V    -670.8mA   -992.8mA   -613.3mA
-1.1V     -398.8mA   -720.8mA   -341.3mA
-930mV    -109.8mA   -431.8mA   -52.32mA
-890mV    -44.91mA   -363.8mA   -23.04mA
-870mV    -28.43mA   -329.8mA   -18.86mA
-760mV    -8.879mA   -142.8mA   -9.749mA
-710mV    -6.383mA   -58.04mA   -7.036mA
-670mV    -4.798mA   -22.41mA   -5.193mA
-610mV    -2.902mA   -7.057mA   -2.962mA
-500mV    -778.4uA   -1.643mA   -611.3uA
6.6V      9.179nA    3.066uA    465pA
| variable   typ   min   max
[Pullup Reference] 3.3V 2.7V 3.6V
| variable   typ   min   max
[Pulldown Reference] 0V 0V 0V
[Pulldown]
-3.3V     -83.56mA   -46.9mA    -96.31mA
-850mV    -82.46mA   -46.9mA    -92.78mA
-710mV    -73.83mA   -46.68mA   -83.86mA
-520mV    -57.22mA   -36.51mA   -66.23mA
0V        30fA       -1pA       200fA
720mV     70.07mA    39.69mA    90.11mA
1.29V     108.2mA    56.55mA    145.7mA
1.84V     125mA      60.7mA     175.1mA
2.21V     127.9mA    61.3mA     181.9mA
4.13V     136.2mA    65.14mA    187.1mA
4.54V     138.3mA    65.14mA    196.8mA
6.6V      138.3mA    65.14mA    196.8mA
[Ramp]
dV/dt_r 1.65116V/273.47182ps 1.18892V/387.81342ps 1.86818V/249.12109ps
dV/dt_f 1.65162V/7.50997ns 1.18895V/17.3243ns 1.8682V/4.92839ns
R_load = 50.0
| Removed startup time: 0s 0s 0s  .
| Removed end time: 35.9ns.
[Rising Waveform]
R_fixture   = 50.0
V_fixture   = 3.3V
V_fixture_min = 2.7V
V_fixture_max = 3.6V
0s        547.3mV    718.4mV    486.3mV
1.7ns     544.6mV    718.4mV    620.8mV
2.1ns     636.6mV    718.2mV    3.173V
2.3ns     1.108V     717.9mV    3.501V
2.6ns     2.858V     716.8mV    3.577V
2.8ns     3.186V     719.8mV    3.587V
3.4ns     3.288V     882.8mV    3.595V
4.1ns     3.295V     2.506V     3.597V
4.7ns     3.297V     2.679V     3.597V
35.9ns    3.3V       2.7V       3.6V
| Removed startup time: 0s 0s 0s  .
| Removed end time: 279.9ns.
[Falling Waveform]
R_fixture   = 50.0
V_fixture   = 3.3V
V_fixture_min = 2.7V
V_fixture_max = 3.6V
0s        3.3V       2.7V       3.6V
5.7ns     3.3V       2.7V       3.584V
7.5ns     3.299V     2.7V       3.239V
9.7ns     3.146V     2.7V       2.381V
12.2ns    2.745V     2.7V       1.421V
14.5ns    2.203V     2.683V     805.7mV
21.4ns    890.3mV    2.479V     531.3mV
41.2ns    578.6mV    1.142V     481.3mV
59.4ns    554.1mV    840.7mV    484.7mV
279.9ns   547.3mV    718.4mV    486.3mV
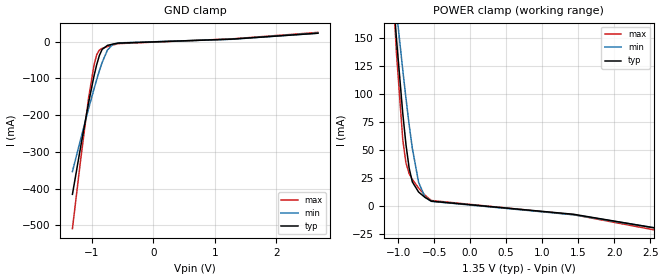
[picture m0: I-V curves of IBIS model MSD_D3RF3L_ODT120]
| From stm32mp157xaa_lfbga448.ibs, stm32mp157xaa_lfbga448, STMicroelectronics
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[Model] MSD_D3RF3L_ODT120
Model_type   Input
C_comp 2.205pF   2.129pF   2.289pF
Vinh = 810.000mV
Vinl = 540.000mV
[Temperature Range]   25.000   125.000   -40.000
[Voltage Range]   1.350V   1.283V   1.450V
[GND Clamp Reference]   0.00V   0.00V   0.00V
[POWER Clamp Reference]   1.350V   1.283V   1.450V
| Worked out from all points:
|   GND clamp passes 1 mA (typ) near -0.44 V on its own axis
|   POWER clamp passes 1 mA (typ) near -0.33 V on its own axis
[GND Clamp]
-1.318V   -415.9mA   -353.7mA   -509.5mA
-1.186V   -288.2mA   -267mA     -324.4mA
-1.055V   -166.2mA   -182.5mA   -153.4mA
-966.7mV  -93.19mA   -128.6mA   -63.66mA
-922.7mV  -62.17mA   -102.9mA   -35.13mA
-878.8mV  -37.21mA   -78.75mA   -22.44mA
-834.9mV  -20.72mA   -56.59mA   -18.05mA
-747mV    -9.669mA   -22.29mA   -13.01mA
-659.1mV  -6.197mA   -6.841mA   -8.642mA
-571.2mV  -3.575mA   -2.923mA   -4.872mA
1.274V    7.315mA    6.948mA    8.004mA
2.68V     23.44mA    23.63mA    25.71mA
[Power Clamp]
-1.33V    430.6mA    371.3mA    519.7mA
-1.155V   265mA      257.2mA    288.9mA
-1.023V   148.8mA    173.8mA    136.1mA
-934.9mV  82.11mA    120.8mA    58.74mA
-890.9mV  54.62mA    95.83mA    38.26mA
-847mV    33.72mA    72.45mA    28.8mA
-803mV    21.45mA    51.48mA    23.65mA
-715.1mV  12.37mA    20.89mA    15.9mA
-627.3mV  7.672mA    8.07mA     9.581mA
-539.4mV  4.255mA    4.103mA    4.846mA
1.438V    -7.434mA   -7.901mA   -7.784mA
2.668V    -20.7mA    -20.54mA   -22.69mA
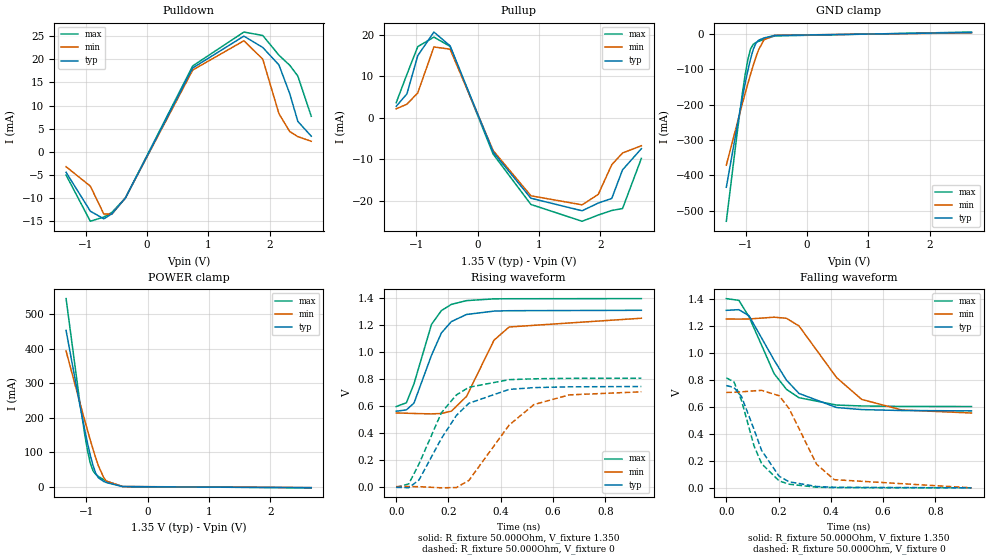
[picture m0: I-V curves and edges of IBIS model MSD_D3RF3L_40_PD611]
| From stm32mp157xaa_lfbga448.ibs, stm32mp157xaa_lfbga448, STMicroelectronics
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[Model] MSD_D3RF3L_40_PD611
Model_type   I/O
C_comp 2.439pF   2.355pF   2.563pF
Vinh = 810.000mV
Vinl = 540.000mV
Vmeas = 675.000mV
Vref = 675.000mV
[Model Spec]
Vinh   810.000mV   777.000mV   860.000mV
Vinl   540.000mV   507.000mV   590.000mV
Vmeas   675.000mV   642.000mV   725.000mV
Vref   675.000mV   642.000mV   725.000mV
[Temperature Range]   25.000   125.000   -40.000
[Voltage Range]   1.350V   1.283V   1.450V
[GND Clamp Reference]   0.00V   0.00V   0.00V
[Pulldown Reference]   0.00V   0.00V   0.00V
[POWER Clamp Reference]   1.350V   1.283V   1.450V
[Pullup Reference]   1.350V   1.283V   1.450V
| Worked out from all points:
|   slope of the pulldown table from 0 to 0.203 V, typ, clamps not added: 35.7 ohm
|   slope of the pullup table from 0 to 0.203 V, typ, clamps not added: 29.7 ohm
|   GND clamp passes 1 mA (typ) near -0.40 V on its own axis
|   POWER clamp passes 1 mA (typ) near -0.41 V on its own axis
|   rising waveform, R_fixture 50.000Ohm, V_fixture 1.350: 20-80 % time 89.7ps typ, 110ps min, 77.2ps max; typ from 0.561 V to 1.31 V
|   rising waveform, R_fixture 50.000Ohm, V_fixture 0: 20-80 % time 144ps typ, 169ps min, 125ps max; typ from -0.005 V to 0.745 V
|   falling waveform, R_fixture 50.000Ohm, V_fixture 1.350: 20-80 % time 143ps typ, 171ps min, 122ps max; typ from 1.32 V to 0.571 V
|   falling waveform, R_fixture 50.000Ohm, V_fixture 0: 20-80 % time 95.6ps typ, 113ps min, 82.6ps max; typ from 0.759 V to 0 V
[GND Clamp]
-1.318V   -433.8mA   -371.2mA   -530.1mA
-1.142V   -261.4mA   -253.4mA   -281.2mA
-1.055V   -178.9mA   -195.9mA   -166mA
-1.011V   -139.7mA   -167.8mA   -114.9mA
-966.7mV  -102.9mA   -140.2mA   -72.01mA
-922.7mV  -70.05mA   -113.7mA   -42.34mA
-878.8mV  -43.4mA    -88.34mA   -28.91mA
-834.9mV  -25.77mA   -64.88mA   -23.94mA
-790.9mV  -17.25mA   -44.21mA   -20.71mA
-703mV    -11.07mA   -16.23mA   -15mA
-527.3mV  -4.022mA   -3.409mA   -5.364mA
2.68V     4.353mA    3.39mA     5.636mA
[Power Clamp]
-1.33V    453mA      393.4mA    545.1mA
-1.111V   242.5mA    247.8mA    251.6mA
-1.023V   162.8mA    190.7mA    148.7mA
-978.8mV  125.6mA    162.8mA    104.1mA
-934.9mV  91.56mA    135.5mA    68.65mA
-890.9mV  62.16mA    109.2mA    47mA
-847mV    39.83mA    84.22mA    36.49mA
-803mV    26.46mA    61.4mA     30.39mA
-715.1mV  15.76mA    26.62mA    20.87mA
-671.2mV  12.53mA    16.52mA    16.7mA
-407.6mV  918uA      1.198mA    1.12mA
2.668V    -2.188mA   -1.824mA   -2.601mA
[Pulldown]
-1.318V   -4.4mA     -3.2mA     -5mA
-922.7mV  -12.81mA   -7.4mA     -14.99mA
-703mV    -14.46mA   -13.41mA   -14.07mA
-571.2mV  -13.39mA   -13.45mA   -13.08mA
-351.5mV  -9.986mA   -9.963mA   -9.957mA
747mV     18.14mA    17.69mA    18.58mA
1.582V    25.02mA    24.02mA    25.9mA
1.889V    22.57mA    20.05mA    25.16mA
2.153V    18.8mA     8.27mA     20.9mA
2.329V    12.6mA     4.4mA      18.73mA
2.461V    6.6mA      3.3mA      16.4mA
2.68V     3.4mA      2.3mA      7.7mA
[Pullup]
-1.33V    2.8mA      2.205mA    3.679mA
-1.155V   5.8mA      3.31mA     10.51mA
-978.8mV  15mA       6.025mA    17.17mA
-715.1mV  20.69mA    17.1mA     19.47mA
-451.5mV  17.37mA    16.56mA    17.24mA
251.5mV   -8.249mA   -7.869mA   -8.719mA
866.7mV   -19.34mA   -18.75mA   -20.84mA
1.702V    -22.36mA   -20.93mA   -24.89mA
1.965V    -20.5mA    -18.41mA   -23.39mA
2.185V    -19.39mA   -11.27mA   -22.29mA
2.361V    -12.5mA    -8.443mA   -21.82mA
2.668V    -7.4mA     -6.7mA     -9.748mA
[Ramp]
R_load=50.000Ohm
dV/dt_r   445.980mV/117.500ps  423.209mV/140.500ps  480.930mV/101.500ps
dV/dt_f   445.980mV/119.500ps  423.209mV/143.500ps  480.930mV/102.500ps
[Rising waveform]
R_fixture=50.000Ohm
V_fixture=1.350
V_fixture_min=1.283
V_fixture_max=1.450
0s        561.1mV    548.4mV    595.8mV
39ps      571.2mV    546.3mV    624.3mV
68ps      621.8mV    544.4mV    765.4mV
135ps     977.4mV    541.3mV    1.207V
173ps     1.144V     544.6mV    1.31V
211ps     1.228V     561.5mV    1.356V
269ps     1.281V     671.4mV    1.384V
374ps     1.306V     1.089V     1.397V
432ps     1.309V     1.188V     1.398V
938ps     1.312V     1.253V     1.399V
[Rising waveform]
R_fixture=50.000Ohm
V_fixture=0
0s        -5.262mV   837.9uV    -4.884mV
48ps      -7.828mV   860.6uV    20.34mV
87ps      49.06mV    -54.49uV   168.2mV
173ps     358.8mV    -8.737mV   550.3mV
230ps     529.3mV    -6.491mV   681.9mV
278ps     620.4mV    46.18mV    739.3mV
432ps     723.5mV    458.2mV    796mV
527ps     736.9mV    610.8mV    802.5mV
662ps     742.6mV    682.8mV    805.7mV
938ps     745.1mV    705.6mV    806.8mV
[Falling waveform]
R_fixture=50.000Ohm
V_fixture=1.350
V_fixture_min=1.283
V_fixture_max=1.450
0s        1.317V     1.253V     1.404V
48ps      1.322V     1.252V     1.391V
87ps      1.276V     1.253V     1.268V
183ps     946.7mV    1.266V     846.8mV
230ps     799.1mV    1.258V     731mV
278ps     700.2mV    1.201V     668.8mV
422ps     595.8mV    817.5mV    614.1mV
518ps     580.6mV    655.9mV    607.4mV
671ps     573.6mV    577.9mV    604mV
938ps     571mV      555.1mV    603.3mV
[Falling waveform]
R_fixture=50.000Ohm
V_fixture=0
0s        758.8mV    707.7mV    815.9mV
29ps      744.9mV    709.1mV    786.6mV
58ps      677.7mV    712.1mV    648.8mV
106ps     433.2mV    719.8mV    311.2mV
135ps     277.3mV    723.2mV    179.2mV
202ps     86mV       683.1mV    51.45mV
240ps     45.01mV    588.7mV    26.82mV
345ps     9.716mV    175.9mV    4.863mV
413ps     3.938mV    60.56mV    1.642mV
938ps     20.48uV    180.3uV    -5.855uV
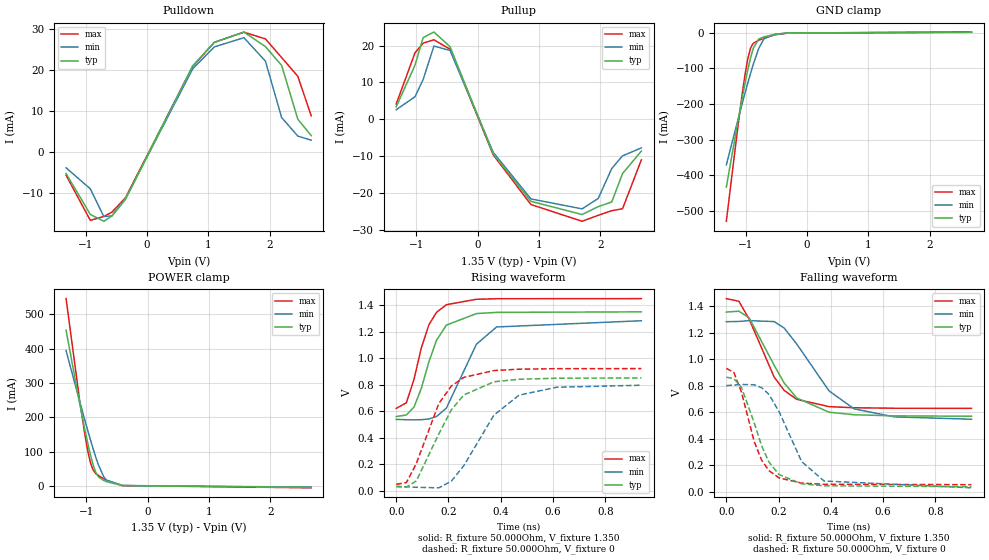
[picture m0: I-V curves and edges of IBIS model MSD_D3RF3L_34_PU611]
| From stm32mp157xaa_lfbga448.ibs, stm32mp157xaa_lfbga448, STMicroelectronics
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[Model] MSD_D3RF3L_34_PU611
Model_type   I/O
C_comp 2.442pF   2.357pF   2.567pF
Vinh = 810.000mV
Vinl = 540.000mV
Vmeas = 675.000mV
Vref = 675.000mV
[Model Spec]
Vinh   810.000mV   777.000mV   860.000mV
Vinl   540.000mV   507.000mV   590.000mV
Vmeas   675.000mV   642.000mV   725.000mV
Vref   675.000mV   642.000mV   725.000mV
[Temperature Range]   25.000   125.000   -40.000
[Voltage Range]   1.350V   1.283V   1.450V
[GND Clamp Reference]   0.00V   0.00V   0.00V
[Pulldown Reference]   0.00V   0.00V   0.00V
[POWER Clamp Reference]   1.350V   1.283V   1.450V
[Pullup Reference]   1.350V   1.283V   1.450V
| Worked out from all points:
|   slope of the pulldown table from 0 to 0.203 V, typ, clamps not added: 31 ohm
|   slope of the pullup table from 0 to 0.203 V, typ, clamps not added: 26.2 ohm
|   GND clamp passes 1 mA (typ) near -0.40 V on its own axis
|   POWER clamp passes 1 mA (typ) near -0.41 V on its own axis
|   rising waveform, R_fixture 50.000Ohm, V_fixture 1.350: 20-80 % time 82.4ps typ, 105ps min, 72ps max; typ from 0.56 V to 1.35 V
|   rising waveform, R_fixture 50.000Ohm, V_fixture 0: 20-80 % time 127ps typ, 152ps min, 112ps max; typ from 0.033 V to 0.851 V
|   falling waveform, R_fixture 50.000Ohm, V_fixture 1.350: 20-80 % time 135ps typ, 168ps min, 119ps max; typ from 1.35 V to 0.57 V
|   falling waveform, R_fixture 50.000Ohm, V_fixture 0: 20-80 % time 92.2ps typ, 113ps min, 80.6ps max; typ from 0.864 V to 0.04 V
[GND Clamp]
-1.318V   -433.7mA   -371.1mA   -530mA
-1.142V   -261.4mA   -253.3mA   -281.2mA
-1.055V   -178.9mA   -195.8mA   -166mA
-1.011V   -139.7mA   -167.7mA   -114.9mA
-966.7mV  -102.9mA   -140.2mA   -71.99mA
-922.7mV  -70.02mA   -113.6mA   -42.32mA
-878.8mV  -43.37mA   -88.29mA   -28.9mA
-790.9mV  -17.22mA   -44.18mA   -20.7mA
-703mV    -11.06mA   -16.21mA   -14.99mA
-527.3mV  -4.011mA   -3.391mA   -5.355mA
-307.6mV  -127.4uA   -187.4uA   -115uA
2.68V     2.164mA    1.839mA    2.56mA
[Power Clamp]
-1.33V    453.1mA    393.6mA    545.2mA
-1.111V   242.6mA    247.9mA    251.6mA
-1.023V   162.8mA    190.9mA    148.7mA
-978.8mV  125.7mA    162.9mA    104.2mA
-934.9mV  91.62mA    135.6mA    68.68mA
-890.9mV  62.22mA    109.2mA    47.04mA
-847mV    39.86mA    84.29mA    36.52mA
-803mV    26.49mA    61.46mA    30.42mA
-715.1mV  15.8mA     26.67mA    20.89mA
-671.2mV  12.56mA    16.56mA    16.71mA
-407.6mV  931.1uA    1.216mA    1.127mA
2.668V    -4.266mA   -3.419mA   -5.488mA
[Pulldown]
-1.318V   -5.2mA     -3.8mA     -5.6mA
-922.7mV  -15.11mA   -8.9mA     -16.55mA
-703mV    -16.77mA   -15.62mA   -15.61mA
-571.2mV  -15.5mA    -15.46mA   -14.57mA
-351.5mV  -11.49mA   -11.33mA   -11.1mA
747mV     20.95mA    20.22mA    20.78mA
1.098V    26.62mA    25.53mA    26.63mA
1.582V    29.14mA    27.77mA    29.11mA
1.933V    25.61mA    22.08mA    27.47mA
2.197V    21.04mA    8.4mA      22.95mA
2.461V    8mA        3.9mA      18.4mA
2.68V     4mA        2.9mA      8.8mA
[Pullup]
-1.33V    3.4mA      2.605mA    4.152mA
-1.023V   14.7mA     6.125mA    18.04mA
-890.9mV  22.15mA    10.79mA    20.65mA
-715.1mV  23.66mA    19.86mA    21.56mA
-451.5mV  19.67mA    18.67mA    18.99mA
251.5mV   -9.374mA   -8.924mA   -9.603mA
866.7mV   -22.22mA   -21.57mA   -23.09mA
1.702V    -25.8mA    -24.27mA   -27.63mA
1.965V    -23.66mA   -21.43mA   -26.01mA
2.185V    -22.4mA    -13.33mA   -24.76mA
2.361V    -14.7mA    -9.89mA    -24.24mA
2.668V    -8.6mA     -7.748mA   -10.98mA
[Ramp]
R_load=50.000Ohm
dV/dt_r   477.540mV/105.000ps  451.386mV/129.000ps  506.379mV/92.000ps
dV/dt_f   477.540mV/113.500ps  451.386mV/141.500ps  506.379mV/100.000ps
[Rising waveform]
R_fixture=50.000Ohm
V_fixture=1.350
V_fixture_min=1.283
V_fixture_max=1.450
0s        559.6mV    538.5mV    621.3mV
39ps      572mV      536mV      664.3mV
68ps      631.1mV    535mV      840.3mV
96ps      772.5mV    536.1mV    1.077V
125ps     971.7mV    541.8mV    1.252V
154ps     1.135V     559.7mV    1.346V
192ps     1.25V      623.7mV    1.404V
307ps     1.337V     1.106V     1.445V
384ps     1.346V     1.236V     1.449V
938ps     1.35V      1.283V     1.45V
[Rising waveform]
R_fixture=50.000Ohm
V_fixture=0
0s        33.44mV    31.33mV    48.63mV
39ps      28.5mV     29.74mV    61.51mV
77ps      74.13mV    26.22mV    205.1mV
163ps     428.5mV    22.06mV    658.1mV
211ps     610.4mV    72.47mV    790.4mV
259ps     723.1mV    190.7mV    855.9mV
374ps     822.4mV    571.1mV    907mV
470ps     841.5mV    721.5mV    917.3mV
614ps     849.1mV    781.1mV    921.3mV
938ps     851.4mV    796.3mV    921.9mV
[Falling waveform]
R_fixture=50.000Ohm
V_fixture=1.350
V_fixture_min=1.283
V_fixture_max=1.450
0s        1.355V     1.282V     1.456V
48ps      1.361V     1.284V     1.436V
87ps      1.312V     1.29V      1.303V
183ps     954.2mV    1.283V     865mV
221ps     821.5mV    1.235V     765.4mV
269ps     708mV      1.115V     697.6mV
393ps     600.7mV    761mV      642.5mV
489ps     581.4mV    625.7mV    634.1mV
642ps     573.1mV    565.4mV    630.4mV
938ps     570.2mV    547.6mV    629.3mV
[Falling waveform]
R_fixture=50.000Ohm
V_fixture=0
0s        864mV      800.8mV    930.8mV
29ps      852.9mV    804.9mV    899.6mV
58ps      787.2mV    809.3mV    751.1mV
106ps     524.5mV    807.4mV    383mV
135ps     347.9mV    785.5mV    239.7mV
163ps     225.4mV    735.1mV    160.8mV
202ps     130.3mV    603.7mV    105.6mV
288ps     61.32mV    229mV      66.74mV
374ps     46.36mV    82.34mV    57.76mV
938ps     39.62mV    31.02mV    54.78mV
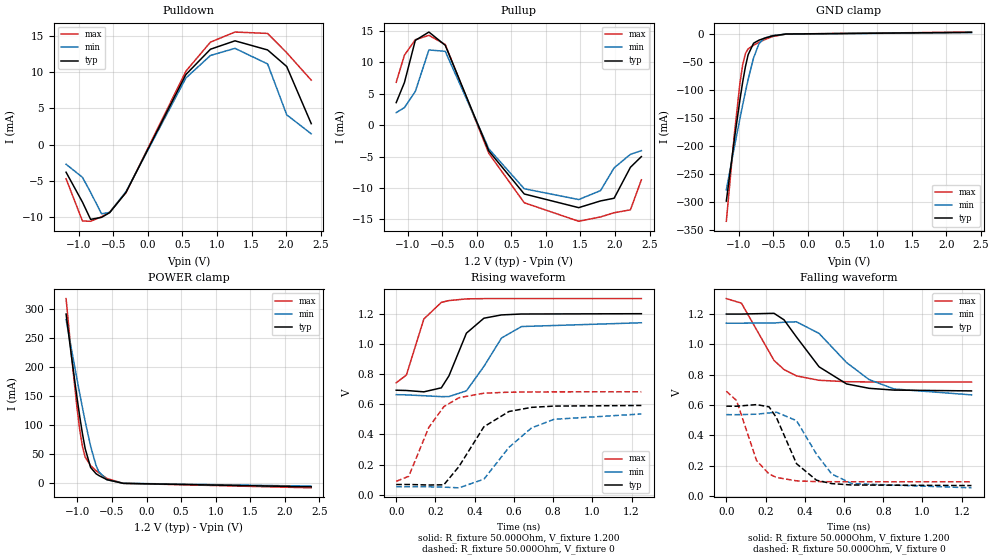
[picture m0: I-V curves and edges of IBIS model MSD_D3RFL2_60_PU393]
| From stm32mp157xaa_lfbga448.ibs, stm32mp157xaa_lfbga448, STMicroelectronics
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[Model] MSD_D3RFL2_60_PU393
Model_type   I/O
C_comp 2.377pF   2.291pF   2.503pF
Vinh = 820.000mV
Vinl = 380.000mV
Vmeas = 600.000mV
Vref = 600.000mV
[Model Spec]
Vinh   820.000mV   790.000mV   870.000mV
Vinl   380.000mV   350.000mV   430.000mV
Vmeas   600.000mV   570.000mV   650.000mV
Vref   600.000mV   570.000mV   650.000mV
[Temperature Range]   25.000   125.000   -40.000
[Voltage Range]   1.200V   1.140V   1.300V
[GND Clamp Reference]   0.00V   0.00V   0.00V
[Pulldown Reference]   0.00V   0.00V   0.00V
[POWER Clamp Reference]   1.200V   1.140V   1.300V
[Pullup Reference]   1.200V   1.140V   1.300V
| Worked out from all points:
|   slope of the pulldown table from 0 to 0.18 V, typ, clamps not added: 50.1 ohm
|   slope of the pullup table from 0 to 0.18 V, typ, clamps not added: 42.9 ohm
|   GND clamp passes 1 mA (typ) near -0.41 V on its own axis
|   POWER clamp passes 1 mA (typ) near -0.41 V on its own axis
|   rising waveform, R_fixture 50.000Ohm, V_fixture 1.200: 20-80 % time 102ps typ, 134ps min, 83.7ps max; typ from 0.693 V to 1.2 V
|   rising waveform, R_fixture 50.000Ohm, V_fixture 0: 20-80 % time 164ps typ, 206ps min, 133ps max; typ from 0.068 V to 0.592 V
|   falling waveform, R_fixture 50.000Ohm, V_fixture 1.200: 20-80 % time 194ps typ, 244ps min, 155ps max; typ from 1.2 V to 0.693 V
|   falling waveform, R_fixture 50.000Ohm, V_fixture 0: 20-80 % time 115ps typ, 143ps min, 97.3ps max; typ from 0.592 V to 0.068 V
[GND Clamp]
-1.182V   -298.8mA   -278.8mA   -334.9mA
-1.064V   -186.6mA   -201.1mA   -176.7mA
-984.9mV  -117.3mA   -151.1mA   -87.88mA
-945.5mV  -85.98mA   -126.9mA   -55.1mA
-906.1mV  -58.6mA    -103.4mA   -35.03mA
-866.7mV  -37.14mA   -81.28mA   -26.65mA
-787.9mV  -16.55mA   -42.62mA   -20.11mA
-709.1mV  -11.11mA   -17.23mA   -15.06mA
-630.3mV  -7.64mA    -7.317mA   -10.42mA
-512.1mV  -3.431mA   -2.91mA    -4.569mA
-315.1mV  -140uA     -201.2uA   -134.4uA
2.364V    2.893mA    2.444mA    3.402mA
[Power Clamp]
-1.164V   291.9mA    282.3mA    318.5mA
-1.085V   218.2mA    230.6mA    219.4mA
-1.006V   148mA      179.8mA    130.6mA
-966.7mV  115.5mA    154.9mA    92.81mA
-927.3mV  85.77mA    130.6mA    63.48mA
-887.9mV  60.06mA    107.1mA    45.4mA
-809.1mV  27.54mA    64.12mA    30.75mA
-730.3mV  16.82mA    31mA       22.11mA
-690.9mV  13.74mA    20.18mA    18.27mA
-572.7mV  6.53mA     6.478mA    8.613mA
-336.4mV  191.9uA    365.4uA    212.3uA
2.382V    -5.79mA    -4.601mA   -7.505mA
[Pulldown]
-1.182V   -3.8mA     -2.7mA     -4.7mA
-945.5mV  -7.91mA    -4.5mA     -10.52mA
-827.3mV  -10.3mA    -6.57mA    -10.56mA
-669.7mV  -10.02mA   -9.53mA    -9.94mA
-551.5mV  -9.371mA   -9.34mA    -9.3mA
-315.1mV  -6.57mA    -6.465mA   -6.612mA
551.5mV   9.679mA    9.199mA    10.14mA
906.1mV   13.16mA    12.3mA     14.14mA
1.261V    14.32mA    13.28mA    15.53mA
1.733V    13.06mA    11.13mA    15.34mA
2.009V    10.78mA    4.12mA     12.68mA
2.364V    2.9mA      1.5mA      8.9mA
[Pullup]
-1.164V   3.6mA      2.005mA    6.838mA
-1.045V   6.8mA      2.809mA    11.16mA
-887.9mV  13.51mA    5.381mA    13.62mA
-690.9mV  14.84mA    11.99mA    14.32mA
-454.5mV  12.73mA    11.77mA    12.85mA
175.8mV   -4.108mA   -3.772mA   -4.491mA
687.9mV   -10.95mA   -10.12mA   -12.35mA
1.476V    -13.13mA   -11.84mA   -15.3mA
1.791V    -12.06mA   -10.42mA   -14.61mA
1.988V    -11.63mA   -6.784mA   -13.94mA
2.224V    -6.7mA     -4.643mA   -13.48mA
2.382V    -5mA       -4.048mA   -8.7mA
[Ramp]
R_load=50.000Ohm
dV/dt_r   309.306mV/133.500ps  287.883mV/171.000ps  341.538mV/108.000ps
dV/dt_f   309.336mV/155.500ps  287.940mV/196.500ps  341.538mV/127.000ps
[Rising waveform]
R_fixture=50.000Ohm
V_fixture=1.200
V_fixture_min=1.140
V_fixture_max=1.300
0s        693.2mV    663.7mV    742.3mV
52ps      691.4mV    662.2mV    793.9mV
141ps     682.4mV    656.7mV    1.165V
230ps     708.9mV    650.6mV    1.275V
269ps     788.6mV    651.1mV    1.287V
358ps     1.071V     689mV      1.298V
447ps     1.17V      850.5mV    1.3V
537ps     1.192V     1.039V     1.3V
639ps     1.198V     1.115V     1.3V
1.25ns    1.2V       1.14V      1.3V
[Rising waveform]
R_fixture=50.000Ohm
V_fixture=0
0s        68.48mV    53.4mV     89.67mV
64ps      68.81mV    53.62mV    123.2mV
166ps     65.22mV    53.41mV    446.3mV
243ps     66.76mV    51.14mV    584.5mV
320ps     187.8mV    46.57mV    643.5mV
447ps     451mV      103.7mV    673.5mV
575ps     552.2mV    314.8mV    680.1mV
690ps     579.6mV    443.6mV    681.7mV
805ps     588.1mV    500.5mV    682.2mV
1.25ns    592.1mV    535.9mV    683mV
[Falling waveform]
R_fixture=50.000Ohm
V_fixture=1.200
V_fixture_min=1.140
V_fixture_max=1.300
0s        1.2V       1.14V      1.302V
77ps      1.2V       1.14V      1.272V
243ps     1.205V     1.141V     894.5mV
294ps     1.162V     1.146V     833.9mV
358ps     1.048V     1.149V     792mV
473ps     851.8mV    1.072V     763mV
613ps     739.1mV    879.9mV    753.7mV
728ps     710.1mV    767.6mV    752.1mV
856ps     698.3mV    705.6mV    751.6mV
1.25ns    693mV      666.8mV    751.5mV
[Falling waveform]
R_fixture=50.000Ohm
V_fixture=0
0s        592.2mV    536.5mV    691mV
52ps      591.9mV    536.1mV    629.6mV
154ps     602.5mV    539.4mV    233.8mV
218ps     587.8mV    547.6mV    144.5mV
256ps     515.3mV    552mV      122mV
358ps     212.6mV    496.6mV    99.47mV
460ps     103.5mV    275mV      94.57mV
537ps     81.42mV    145.1mV    93.73mV
639ps     72.18mV    81.37mV    93.4mV
1.25ns    68.4mV     53.42mV    93.25mV
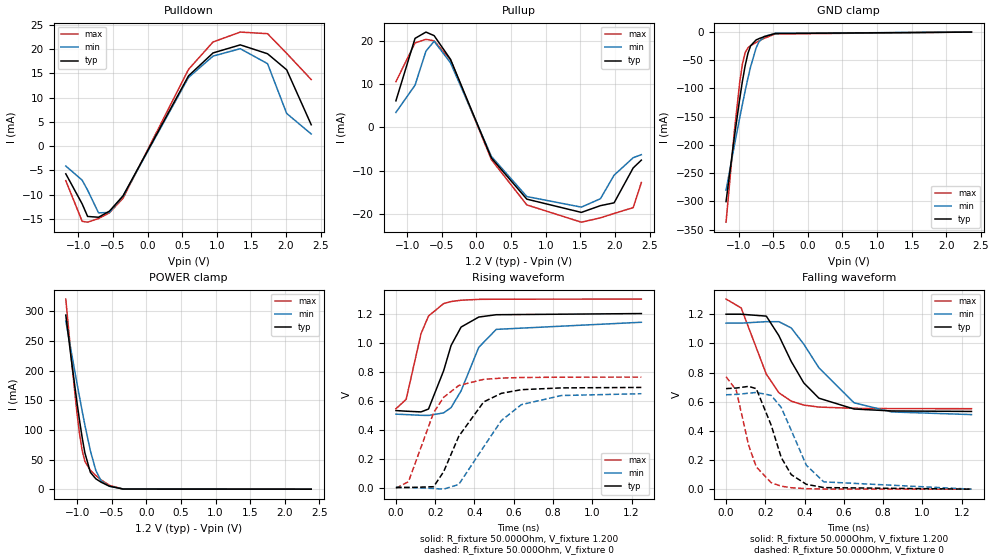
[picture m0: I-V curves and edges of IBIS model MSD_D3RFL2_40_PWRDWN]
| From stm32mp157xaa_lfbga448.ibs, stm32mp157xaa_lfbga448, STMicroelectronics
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[Model] MSD_D3RFL2_40_PWRDWN
Model_type   I/O
C_comp 2.581pF   2.493pF   2.708pF
Vinh = 820.000mV
Vinl = 380.000mV
Vmeas = 600.000mV
Vref = 600.000mV
[Model Spec]
Vinh   820.000mV   790.000mV   870.000mV
Vinl   380.000mV   350.000mV   430.000mV
Vmeas   600.000mV   570.000mV   650.000mV
Vref   600.000mV   570.000mV   650.000mV
[Temperature Range]   25.000   125.000   -40.000
[Voltage Range]   1.200V   1.140V   1.300V
[GND Clamp Reference]   0.00V   0.00V   0.00V
[Pulldown Reference]   0.00V   0.00V   0.00V
[POWER Clamp Reference]   1.200V   1.140V   1.300V
[Pullup Reference]   1.200V   1.140V   1.300V
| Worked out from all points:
|   slope of the pulldown table from 0 to 0.18 V, typ, clamps not added: 35.6 ohm
|   slope of the pullup table from 0 to 0.18 V, typ, clamps not added: 29.6 ohm
|   GND clamp passes 1 mA (typ) near -0.40 V on its own axis
|   POWER clamp passes 1 mA (typ) near -0.41 V on its own axis
|   rising waveform, R_fixture 50.000Ohm, V_fixture 1.200: 20-80 % time 97ps typ, 124ps min, 83.3ps max; typ from 0.531 V to 1.2 V
|   rising waveform, R_fixture 50.000Ohm, V_fixture 0: 20-80 % time 162ps typ, 193ps min, 140ps max; typ from 0.001 V to 0.69 V
|   falling waveform, R_fixture 50.000Ohm, V_fixture 1.200: 20-80 % time 171ps typ, 212ps min, 139ps max; typ from 1.2 V to 0.533 V
|   falling waveform, R_fixture 50.000Ohm, V_fixture 0: 20-80 % time 106ps typ, 130ps min, 89.7ps max; typ from 0.69 V to 0 V
[GND Clamp]
-1.182V   -300.5mA   -280.4mA   -337mA
-1.064V   -188.1mA   -202.5mA   -178.5mA
-984.9mV  -118.6mA   -152.2mA   -89.49mA
-945.5mV  -87.16mA   -127.9mA   -56.6mA
-906.1mV  -59.71mA   -104.4mA   -36.4mA
-866.7mV  -38.14mA   -82.14mA   -27.92mA
-827.3mV  -24.29mA   -61.54mA   -24.05mA
-748.5mV  -14mA      -28.45mA   -18.47mA
-709.1mV  -11.76mA   -17.8mA    -15.89mA
-630.3mV  -8.132mA   -7.75mA    -11.05mA
-472.7mV  -2.557mA   -2.242mA   -3.323mA
2.364V    29.58nA    484.6nA    2.864nA
[Power Clamp]
-1.164V   293.6mA    283.6mA    320.6mA
-1.085V   219.6mA    231.9mA    221.3mA
-1.006V   149.3mA    180.9mA    132.2mA
-966.7mV  116.7mA    156mA      94.33mA
-927.3mV  86.87mA    131.6mA    64.9mA
-887.9mV  61.07mA    108mA      46.71mA
-809.1mV  28.38mA    64.84mA    31.83mA
-730.3mV  17.49mA    31.58mA    22.97mA
-651.5mV  11.58mA    13.7mA     15.38mA
-533.3mV  4.956mA    4.897mA    6.46mA
-336.4mV  215.7uA    403.7uA    242.8uA
2.382V    -24.83nA   -515.5nA   -2.721nA
[Pulldown]
-1.182V   -5.7mA     -4.1mA     -7.1mA
-945.5mV  -11.89mA   -7mA       -15.47mA
-866.7mV  -14.47mA   -9.06mA    -15.65mA
-709.1mV  -14.63mA   -13.73mA   -14.9mA
-551.5mV  -13.38mA   -13.65mA   -13.72mA
-354.6mV  -10.22mA   -10.29mA   -10.71mA
590.9mV   14.46mA    14.13mA    15.79mA
945.5mV   19.18mA    18.53mA    21.44mA
1.339V    20.84mA    20.05mA    23.47mA
1.733V    19.01mA    16.97mA    23.14mA
2.009V    15.71mA    6.73mA     19.1mA
2.364V    4.4mA      2.5mA      13.7mA
[Pullup]
-1.164V   6.1mA      3.409mA    10.51mA
-887.9mV  20.51mA    9.705mA    19.46mA
-730.3mV  21.96mA    17.56mA    20.29mA
-612.1mV  21.14mA    19.85mA    19.94mA
-375.8mV  15.68mA    14.87mA    15.58mA
215.2mV   -7.105mA   -6.743mA   -7.481mA
727.3mV   -16.61mA   -16.01mA   -17.94mA
1.515V    -19.67mA   -18.45mA   -21.93mA
1.791V    -18.11mA   -16.51mA   -20.92mA
1.988V    -17.46mA   -11.08mA   -19.92mA
2.264V    -9.4mA     -7.043mA   -18.57mA
2.382V    -7.6mA     -6.348mA   -12.78mA
[Ramp]
R_load=50.000Ohm
dV/dt_r   407.310mV/130.000ps  383.549mV/159.500ps  452.790mV/112.000ps
dV/dt_f   407.310mV/139.500ps  383.518mV/172.500ps  452.790mV/115.000ps
[Rising waveform]
R_fixture=50.000Ohm
V_fixture=1.200
V_fixture_min=1.140
V_fixture_max=1.300
0s        531mV      506.3mV    543.3mV
52ps      526.6mV    503.2mV    608.1mV
128ps     521.7mV    498.2mV    1.062V
166ps     541.6mV    497.3mV    1.183V
243ps     805.9mV    515mV      1.269V
281ps     980.2mV    551.7mV    1.283V
332ps     1.107V     667.3mV    1.292V
422ps     1.176V     967.3mV    1.298V
511ps     1.192V     1.091V     1.299V
1.25ns    1.2V       1.14V      1.3V
[Rising waveform]
R_fixture=50.000Ohm
V_fixture=0
0s        805.1uV    820.2uV    -5.393mV
64ps      105.2uV    795.2uV    40.78mV
192ps     5.82mV     -6.556mV   516.7mV
243ps     109.2mV    -11.18mV   622.5mV
320ps     353.3mV    21.21mV    703.5mV
447ps     590.8mV    280.6mV    746.4mV
537ps     649.8mV    462.1mV    754.9mV
639ps     675mV      571.9mV    759mV
843ps     687.4mV    634.7mV    761.2mV
1.25ns    690.4mV    647.2mV    761.5mV
[Falling waveform]
R_fixture=50.000Ohm
V_fixture=1.200
V_fixture_min=1.140
V_fixture_max=1.300
0s        1.2V       1.139V     1.304V
77ps      1.2V       1.139V     1.243V
205ps     1.187V     1.149V     789mV
269ps     1.053V     1.149V     661.5mV
332ps     876mV      1.106V     603.9mV
396ps     728.8mV    994.4mV    576.8mV
473ps     624mV      832.4mV    563.2mV
652ps     549.8mV    592.6mV    554.5mV
843ps     536.6mV    529.8mV    552.5mV
1.25ns    533.1mV    511.5mV    552.2mV
[Falling waveform]
R_fixture=50.000Ohm
V_fixture=0
0s        689.8mV    647.4mV    771.4mV
52ps      693.6mV    650mV      678.7mV
115ps     705.1mV    658.1mV    301.3mV
154ps     689.3mV    663.4mV    152.9mV
230ps     438.4mV    643.5mV    44.08mV
281ps     217.3mV    560.4mV    20.54mV
332ps     99.61mV    404mV      9.788mV
409ps     33.3mV     163.8mV    3.227mV
498ps     10.82mV    50.02mV    921uV
1.25ns    7.551uV    40.79uV    2.397uV
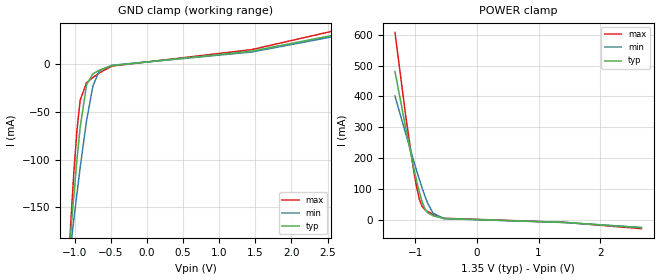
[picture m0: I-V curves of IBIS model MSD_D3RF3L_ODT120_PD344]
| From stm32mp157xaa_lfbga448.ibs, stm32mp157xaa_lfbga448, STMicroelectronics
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[Model] MSD_D3RF3L_ODT120_PD344
Model_type   Input
C_comp 2.291pF   2.213pF   2.379pF
Vinh = 810.000mV
Vinl = 540.000mV
[Model Spec]
Vinh   810.000mV   777.000mV   860.000mV
Vinl   540.000mV   507.000mV   590.000mV
[Temperature Range]   25.000   125.000   -40.000
[Voltage Range]   1.350V   1.283V   1.450V
[GND Clamp Reference]   0.00V   0.00V   0.00V
[POWER Clamp Reference]   1.350V   1.283V   1.450V
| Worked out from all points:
|   GND clamp passes 1 mA (typ) near -0.43 V on its own axis
|   POWER clamp passes 1 mA (typ) near -0.31 V on its own axis
[GND Clamp]
-1.318V   -445.8mA   -370.9mA   -564.1mA
-1.098V   -220.9mA   -220.9mA   -229.2mA
-1.055V   -178.2mA   -191.6mA   -168.5mA
-1.011V   -137.4mA   -163mA     -113.9mA
-966.7mV  -99.47mA   -135mA     -68.66mA
-922.7mV  -65.98mA   -108.1mA   -37.82mA
-834.9mV  -21.92mA   -59.28mA   -19.7mA
-747mV    -10.38mA   -23.26mA   -14.25mA
-659.1mV  -6.698mA   -7.22mA    -9.504mA
-483.3mV  -1.78mA    -1.515mA   -2.315mA
1.45V     13.31mA    12.39mA    14.92mA
2.68V     31.43mA    29.92mA    36.14mA
[Power Clamp]
-1.33V    480.8mA    401.3mA    607.3mA
-1.155V   297.2mA    278.9mA    335.6mA
-1.023V   166.1mA    189.2mA    155.7mA
-978.8mV  126.4mA    160.1mA    106.5mA
-934.9mV  90.59mA    131.7mA    67.72mA
-890.9mV  60.09mA    104.4mA    44.56mA
-847mV    37.23mA    78.91mA    33.7mA
-803mV    23.89mA    55.99mA    27.65mA
-715.1mV  13.9mA     22.63mA    18.54mA
-539.4mV  4.776mA    4.471mA    5.686mA
1.438V    -7.768mA   -8.34mA    -7.847mA
2.668V    -25.07mA   -24.13mA   -28.02mA
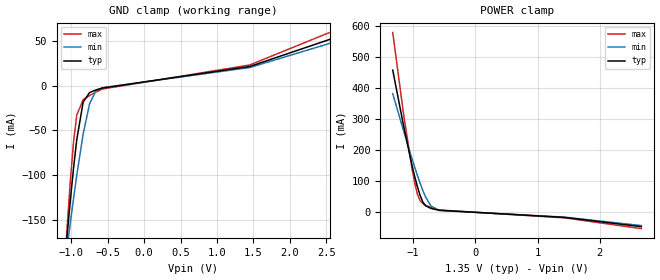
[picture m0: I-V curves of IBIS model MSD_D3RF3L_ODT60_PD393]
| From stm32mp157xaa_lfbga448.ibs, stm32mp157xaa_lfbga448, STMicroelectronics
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[Model] MSD_D3RF3L_ODT60_PD393
Model_type   Input
C_comp 2.317pF   2.267pF   2.384pF
Vinh = 810.000mV
Vinl = 540.000mV
[Temperature Range]   25.000   125.000   -40.000
[Voltage Range]   1.350V   1.283V   1.450V
[GND Clamp Reference]   0.00V   0.00V   0.00V
[POWER Clamp Reference]   1.350V   1.283V   1.450V
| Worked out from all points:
|   GND clamp passes 1 mA (typ) near -0.46 V on its own axis
|   POWER clamp passes 1 mA (typ) near -0.18 V on its own axis
[GND Clamp]
-1.318V   -429.2mA   -356.3mA   -544.4mA
-1.098V   -208.7mA   -209.3mA   -216.2mA
-1.055V   -167.2mA   -180.8mA   -158.3mA
-1.011V   -128.1mA   -153mA     -106.4mA
-966.7mV  -91.95mA   -126mA     -62.96mA
-922.7mV  -60.4mA    -100mA     -32.93mA
-834.9mV  -18.41mA   -53.9mA    -15.77mA
-747mV    -7.782mA   -20.42mA   -11.12mA
-659.1mV  -4.84mA    -5.734mA   -7.17mA
-571.2mV  -2.728mA   -2.377mA   -3.872mA
1.45V     21.29mA    20.11mA    22.99mA
2.68V     55.12mA    50.3mA     63.65mA
[Power Clamp]
-1.33V    458.3mA    382.4mA    579.7mA
-1.155V   278.8mA    262.4mA    315.8mA
-1.023V   154.2mA    175.3mA    144.9mA
-978.8mV  117.4mA    147.3mA    97.39mA
-934.9mV  84.15mA    120.3mA    60.04mA
-890.9mV  55.47mA    94.73mA    38.04mA
-847mV    33.77mA    71.14mA    28.23mA
-803mV    21.28mA    50.29mA    23.14mA
-715.1mV  12.6mA     20.38mA    15.73mA
-583.3mV  6.778mA    6.037mA    7.519mA
1.438V    -16.37mA   -15.58mA   -17.88mA
2.668V    -46.16mA   -42.63mA   -52.57mA
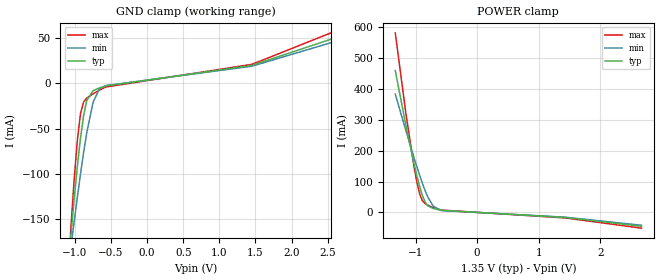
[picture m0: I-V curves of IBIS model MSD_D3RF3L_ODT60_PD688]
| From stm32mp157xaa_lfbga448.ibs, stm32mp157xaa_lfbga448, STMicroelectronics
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[Model] MSD_D3RF3L_ODT60_PD688
Model_type   Input
C_comp 2.406pF   2.355pF   2.476pF
Vinh = 810.000mV
Vinl = 540.000mV
[Temperature Range]   25.000   125.000   -40.000
[Voltage Range]   1.350V   1.283V   1.450V
[GND Clamp Reference]   0.00V   0.00V   0.00V
[POWER Clamp Reference]   1.350V   1.283V   1.450V
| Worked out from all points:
|   GND clamp passes 1 mA (typ) near -0.45 V on its own axis
|   POWER clamp passes 1 mA (typ) near -0.18 V on its own axis
[GND Clamp]
-1.318V   -430.1mA   -357mA     -545.5mA
-1.055V   -167.8mA   -181.3mA   -159mA
-1.011V   -128.6mA   -153.4mA   -107.1mA
-966.7mV  -92.53mA   -126.3mA   -63.57mA
-922.7mV  -60.85mA   -100.5mA   -33.55mA
-878.8mV  -35.44mA   -76.18mA   -20.55mA
-834.9mV  -18.78mA   -54.21mA   -16.27mA
-747mV    -8.075mA   -20.66mA   -11.53mA
-659.1mV  -5.055mA   -5.916mA   -7.48mA
-571.2mV  -2.875mA   -2.501mA   -4.084mA
1.45V     19.71mA    18.86mA    20.93mA
2.68V     52.24mA    48.01mA    59.9mA
[Power Clamp]
-1.33V    459.2mA    383.2mA    580.9mA
-1.155V   279.6mA    263.1mA    316.7mA
-1.023V   154.8mA    175.9mA    145.6mA
-978.8mV  118.1mA    147.8mA    98.08mA
-934.9mV  84.71mA    120.8mA    60.6mA
-890.9mV  55.92mA    95.15mA    38.58mA
-847mV    34.17mA    71.55mA    28.73mA
-803mV    21.64mA    50.66mA    23.59mA
-715.1mV  12.89mA    20.67mA    16.07mA
-583.3mV  6.942mA    6.219mA    7.713mA
1.438V    -16.27mA   -15.44mA   -17.88mA
2.668V    -44.69mA   -41.41mA   -50.8mA
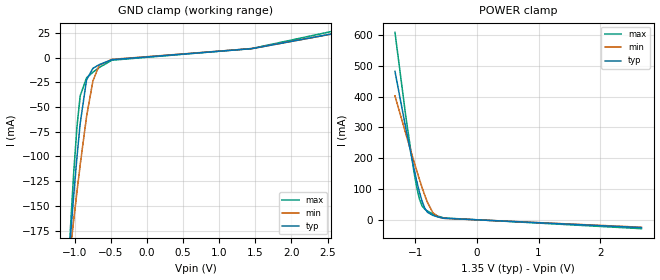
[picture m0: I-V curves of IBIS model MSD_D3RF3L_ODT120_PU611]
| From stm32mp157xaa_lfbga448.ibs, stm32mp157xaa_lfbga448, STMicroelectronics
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[Model] MSD_D3RF3L_ODT120_PU611
Model_type   Input
C_comp 2.400pF   2.320pF   2.491pF
Vinh = 810.000mV
Vinl = 540.000mV
[Temperature Range]   25.000   125.000   -40.000
[Voltage Range]   1.350V   1.283V   1.450V
[GND Clamp Reference]   0.00V   0.00V   0.00V
[POWER Clamp Reference]   1.350V   1.283V   1.450V
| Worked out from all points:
|   GND clamp passes 1 mA (typ) near -0.43 V on its own axis
|   POWER clamp passes 1 mA (typ) near -0.31 V on its own axis
[GND Clamp]
-1.318V   -446.8mA   -371.6mA   -565.4mA
-1.098V   -221.5mA   -221.4mA   -230.1mA
-1.055V   -178.9mA   -192.1mA   -169.3mA
-1.011V   -138mA     -163.4mA   -114.7mA
-966.7mV  -100mA     -135.4mA   -69.39mA
-922.7mV  -66.49mA   -108.4mA   -38.49mA
-834.9mV  -22.33mA   -59.59mA   -20.26mA
-747mV    -10.7mA    -23.51mA   -14.69mA
-659.1mV  -6.936mA   -7.401mA   -9.836mA
-483.3mV  -1.877mA   -1.587mA   -2.447mA
1.45V     9.232mA    9.294mA    9.417mA
2.68V     25.83mA    25.71mA    28.64mA
[Power Clamp]
-1.33V    482.1mA    402.3mA    608.7mA
-1.155V   298.1mA    279.8mA    336.7mA
-1.023V   166.9mA    189.9mA    156.7mA
-978.8mV  127.1mA    160.7mA    107.4mA
-934.9mV  91.21mA    132.3mA    68.51mA
-890.9mV  60.7mA     105mA      45.27mA
-847mV    37.77mA    79.43mA    34.35mA
-803mV    24.39mA    56.46mA    28.23mA
-715.1mV  14.28mA    22.99mA    18.97mA
-627.3mV  8.907mA    9.059mA    11.5mA
-539.4mV  4.962mA    4.662mA    5.889mA
2.668V    -25.45mA   -24.3mA    -28.89mA
